VERSION 5.7 ;
  NOWIREEXTENSIONATPIN ON ;
  DIVIDERCHAR "/" ;
  BUSBITCHARS "[]" ;
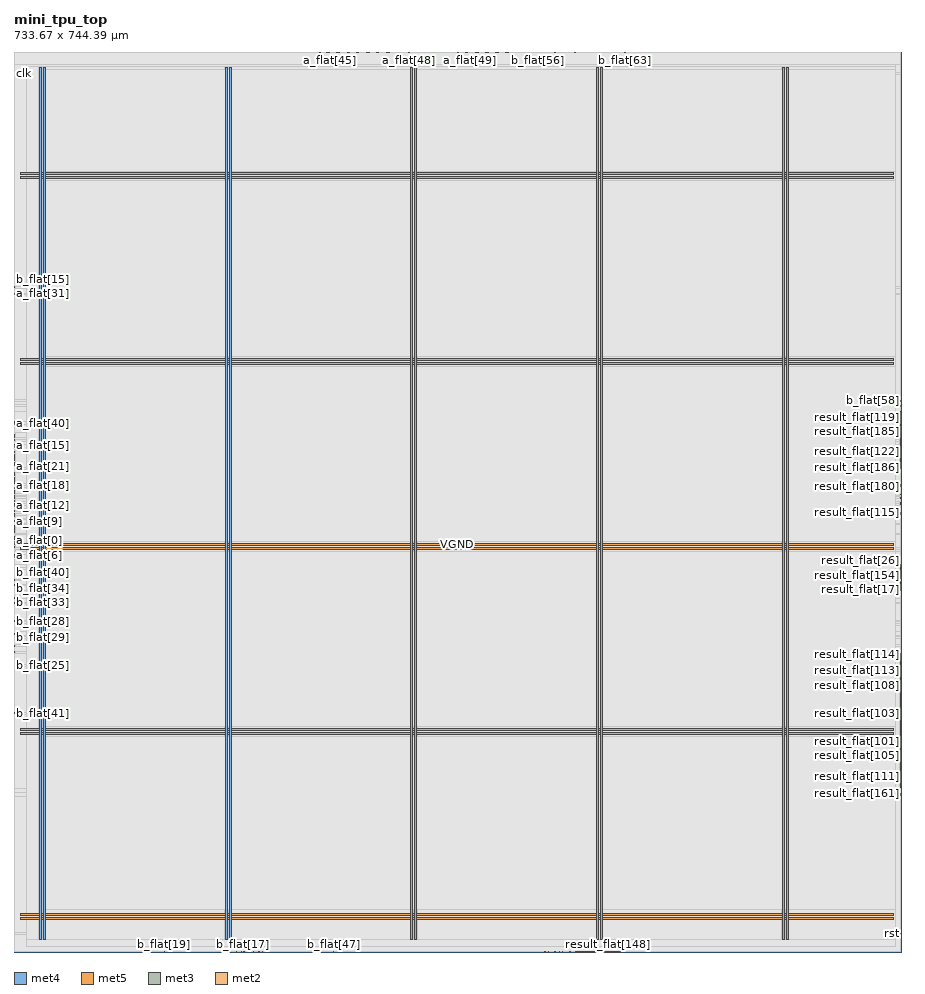
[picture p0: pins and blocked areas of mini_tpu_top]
MACRO mini_tpu_top
  CLASS BLOCK ;
  FOREIGN mini_tpu_top ;
  ORIGIN 0.000 0.000 ;
  SIZE 733.670 BY 744.390 ;
  PIN VGND
    DIRECTION INOUT ;
    USE GROUND ;
    PORT
      LAYER met4 ;
        RECT 24.340 10.640 25.940 731.920 ;
    END
    PORT
      LAYER met4 ;
        RECT 177.940 10.640 179.540 731.920 ;
    END
    PORT
      LAYER met4 ;
        RECT 331.540 10.640 333.140 731.920 ;
    END
    PORT
      LAYER met4 ;
        RECT 485.140 10.640 486.740 731.920 ;
    END
    PORT
      LAYER met4 ;
        RECT 638.740 10.640 640.340 731.920 ;
    END
    PORT
      LAYER met5 ;
        RECT 5.520 30.030 727.720 31.630 ;
    END
    PORT
      LAYER met5 ;
        RECT 5.520 183.210 727.720 184.810 ;
    END
    PORT
      LAYER met5 ;
        RECT 5.520 336.390 727.720 337.990 ;
    END
    PORT
      LAYER met5 ;
        RECT 5.520 489.570 727.720 491.170 ;
    END
    PORT
      LAYER met5 ;
        RECT 5.520 642.750 727.720 644.350 ;
    END
  END VGND
  PIN VPWR
    DIRECTION INOUT ;
    USE POWER ;
    PORT
      LAYER met4 ;
        RECT 21.040 10.640 22.640 731.920 ;
    END
    PORT
      LAYER met4 ;
        RECT 174.640 10.640 176.240 731.920 ;
    END
    PORT
      LAYER met4 ;
        RECT 328.240 10.640 329.840 731.920 ;
    END
    PORT
      LAYER met4 ;
        RECT 481.840 10.640 483.440 731.920 ;
    END
    PORT
      LAYER met4 ;
        RECT 635.440 10.640 637.040 731.920 ;
    END
    PORT
      LAYER met5 ;
        RECT 5.520 26.730 727.720 28.330 ;
    END
    PORT
      LAYER met5 ;
        RECT 5.520 179.910 727.720 181.510 ;
    END
    PORT
      LAYER met5 ;
        RECT 5.520 333.090 727.720 334.690 ;
    END
    PORT
      LAYER met5 ;
        RECT 5.520 486.270 727.720 487.870 ;
    END
    PORT
      LAYER met5 ;
        RECT 5.520 639.450 727.720 641.050 ;
    END
  END VPWR
  PIN a_flat[0]
    DIRECTION INPUT ;
    USE SIGNAL ;
    ANTENNAGATEAREA 0.213000 ;
    PORT
      LAYER met3 ;
        RECT 0.000 340.040 0.600 340.640 ;
    END
  END a_flat[0]
  PIN a_flat[10]
    DIRECTION INPUT ;
    USE SIGNAL ;
    ANTENNAGATEAREA 0.213000 ;
    PORT
      LAYER met3 ;
        RECT 0.000 355.000 0.600 355.600 ;
    END
  END a_flat[10]
  PIN a_flat[11]
    DIRECTION INPUT ;
    USE SIGNAL ;
    ANTENNAGATEAREA 0.647700 ;
    ANTENNADIFFAREA 0.434700 ;
    PORT
      LAYER met3 ;
        RECT 0.000 348.200 0.600 348.800 ;
    END
  END a_flat[11]
  PIN a_flat[12]
    DIRECTION INPUT ;
    USE SIGNAL ;
    ANTENNAGATEAREA 0.213000 ;
    PORT
      LAYER met3 ;
        RECT 0.000 368.600 0.600 369.200 ;
    END
  END a_flat[12]
  PIN a_flat[13]
    DIRECTION INPUT ;
    USE SIGNAL ;
    ANTENNAGATEAREA 0.213000 ;
    PORT
      LAYER met3 ;
        RECT 0.000 359.080 0.600 359.680 ;
    END
  END a_flat[13]
  PIN a_flat[14]
    DIRECTION INPUT ;
    USE SIGNAL ;
    ANTENNAGATEAREA 0.213000 ;
    PORT
      LAYER met3 ;
        RECT 0.000 344.120 0.600 344.720 ;
    END
  END a_flat[14]
  PIN a_flat[15]
    DIRECTION INPUT ;
    USE SIGNAL ;
    ANTENNAGATEAREA 0.213000 ;
    PORT
      LAYER met3 ;
        RECT 0.000 418.920 0.600 419.520 ;
    END
  END a_flat[15]
  PIN a_flat[16]
    DIRECTION INPUT ;
    USE SIGNAL ;
    ANTENNAGATEAREA 0.213000 ;
    PORT
      LAYER met3 ;
        RECT 0.000 405.320 0.600 405.920 ;
    END
  END a_flat[16]
  PIN a_flat[17]
    DIRECTION INPUT ;
    USE SIGNAL ;
    ANTENNAGATEAREA 0.647700 ;
    ANTENNADIFFAREA 0.434700 ;
    PORT
      LAYER met3 ;
        RECT 0.000 335.960 0.600 336.560 ;
    END
  END a_flat[17]
  PIN a_flat[18]
    DIRECTION INPUT ;
    USE SIGNAL ;
    ANTENNAGATEAREA 0.213000 ;
    PORT
      LAYER met3 ;
        RECT 0.000 379.480 0.600 380.080 ;
    END
  END a_flat[18]
  PIN a_flat[19]
    DIRECTION INPUT ;
    USE SIGNAL ;
    ANTENNAGATEAREA 0.213000 ;
    PORT
      LAYER met3 ;
        RECT 0.000 394.440 0.600 395.040 ;
    END
  END a_flat[19]
  PIN a_flat[1]
    DIRECTION INPUT ;
    USE SIGNAL ;
    ANTENNAGATEAREA 0.213000 ;
    PORT
      LAYER met3 ;
        RECT 0.000 341.400 0.600 342.000 ;
    END
  END a_flat[1]
  PIN a_flat[20]
    DIRECTION INPUT ;
    USE SIGNAL ;
    ANTENNAGATEAREA 0.213000 ;
    PORT
      LAYER met3 ;
        RECT 0.000 378.120 0.600 378.720 ;
    END
  END a_flat[20]
  PIN a_flat[21]
    DIRECTION INPUT ;
    USE SIGNAL ;
    ANTENNAGATEAREA 0.213000 ;
    PORT
      LAYER met3 ;
        RECT 0.000 401.240 0.600 401.840 ;
    END
  END a_flat[21]
  PIN a_flat[22]
    DIRECTION INPUT ;
    USE SIGNAL ;
    ANTENNAGATEAREA 0.213000 ;
    PORT
      LAYER met3 ;
        RECT 0.000 382.200 0.600 382.800 ;
    END
  END a_flat[22]
  PIN a_flat[23]
    DIRECTION INPUT ;
    USE SIGNAL ;
    ANTENNAGATEAREA 0.213000 ;
    PORT
      LAYER met3 ;
        RECT 0.000 427.080 0.600 427.680 ;
    END
  END a_flat[23]
  PIN a_flat[24]
    DIRECTION INPUT ;
    USE SIGNAL ;
    ANTENNAGATEAREA 0.213000 ;
    PORT
      LAYER met3 ;
        RECT 0.000 389.000 0.600 389.600 ;
    END
  END a_flat[24]
  PIN a_flat[25]
    DIRECTION INPUT ;
    USE SIGNAL ;
    ANTENNAGATEAREA 0.213000 ;
    PORT
      LAYER met3 ;
        RECT 0.000 375.400 0.600 376.000 ;
    END
  END a_flat[25]
  PIN a_flat[26]
    DIRECTION INPUT ;
    USE SIGNAL ;
    ANTENNAGATEAREA 0.213000 ;
    PORT
      LAYER met3 ;
        RECT 0.000 406.680 0.600 407.280 ;
    END
  END a_flat[26]
  PIN a_flat[27]
    DIRECTION INPUT ;
    USE SIGNAL ;
    ANTENNAGATEAREA 0.213000 ;
    PORT
      LAYER met3 ;
        RECT 0.000 395.800 0.600 396.400 ;
    END
  END a_flat[27]
  PIN a_flat[28]
    DIRECTION INPUT ;
    USE SIGNAL ;
    ANTENNAGATEAREA 0.213000 ;
    PORT
      LAYER met3 ;
        RECT 0.000 437.960 0.600 438.560 ;
    END
  END a_flat[28]
  PIN a_flat[29]
    DIRECTION INPUT ;
    USE SIGNAL ;
    ANTENNAGATEAREA 0.213000 ;
    PORT
      LAYER met3 ;
        RECT 0.000 417.560 0.600 418.160 ;
    END
  END a_flat[29]
  PIN a_flat[2]
    DIRECTION INPUT ;
    USE SIGNAL ;
    ANTENNAGATEAREA 0.213000 ;
    PORT
      LAYER met3 ;
        RECT 0.000 337.320 0.600 337.920 ;
    END
  END a_flat[2]
  PIN a_flat[30]
    DIRECTION INPUT ;
    USE SIGNAL ;
    ANTENNAGATEAREA 0.213000 ;
    PORT
      LAYER met3 ;
        RECT 0.000 386.280 0.600 386.880 ;
    END
  END a_flat[30]
  PIN a_flat[31]
    DIRECTION INPUT ;
    USE SIGNAL ;
    ANTENNAGATEAREA 0.213000 ;
    PORT
      LAYER met3 ;
        RECT 0.000 544.040 0.600 544.640 ;
    END
  END a_flat[31]
  PIN a_flat[32]
    DIRECTION INPUT ;
    USE SIGNAL ;
    ANTENNAGATEAREA 0.213000 ;
    PORT
      LAYER met2 ;
        RECT 266.890 744.110 267.170 744.390 ;
    END
  END a_flat[32]
  PIN a_flat[33]
    DIRECTION INPUT ;
    USE SIGNAL ;
    ANTENNAGATEAREA 0.213000 ;
    PORT
      LAYER met3 ;
        RECT 0.000 416.200 0.600 416.800 ;
    END
  END a_flat[33]
  PIN a_flat[34]
    DIRECTION INPUT ;
    USE SIGNAL ;
    ANTENNAGATEAREA 0.213000 ;
    PORT
      LAYER met2 ;
        RECT 264.130 744.110 264.410 744.390 ;
    END
  END a_flat[34]
  PIN a_flat[35]
    DIRECTION INPUT ;
    USE SIGNAL ;
    ANTENNAGATEAREA 0.213000 ;
    PORT
      LAYER met3 ;
        RECT 0.000 383.560 0.600 384.160 ;
    END
  END a_flat[35]
  PIN a_flat[36]
    DIRECTION INPUT ;
    USE SIGNAL ;
    ANTENNAGATEAREA 0.213000 ;
    PORT
      LAYER met3 ;
        RECT 0.000 387.640 0.600 388.240 ;
    END
  END a_flat[36]
  PIN a_flat[37]
    DIRECTION INPUT ;
    USE SIGNAL ;
    ANTENNAGATEAREA 0.213000 ;
    PORT
      LAYER met2 ;
        RECT 245.730 744.110 246.010 744.390 ;
    END
  END a_flat[37]
  PIN a_flat[38]
    DIRECTION INPUT ;
    USE SIGNAL ;
    ANTENNAGATEAREA 0.213000 ;
    PORT
      LAYER met3 ;
        RECT 0.000 409.400 0.600 410.000 ;
    END
  END a_flat[38]
  PIN a_flat[39]
    DIRECTION INPUT ;
    USE SIGNAL ;
    ANTENNAGATEAREA 0.213000 ;
    PORT
      LAYER met2 ;
        RECT 250.330 744.110 250.610 744.390 ;
    END
  END a_flat[39]
  PIN a_flat[3]
    DIRECTION INPUT ;
    USE SIGNAL ;
    ANTENNAGATEAREA 0.213000 ;
    PORT
      LAYER met3 ;
        RECT 0.000 346.840 0.600 347.440 ;
    END
  END a_flat[3]
  PIN a_flat[40]
    DIRECTION INPUT ;
    USE SIGNAL ;
    ANTENNAGATEAREA 0.213000 ;
    PORT
      LAYER met3 ;
        RECT 0.000 436.600 0.600 437.200 ;
    END
  END a_flat[40]
  PIN a_flat[41]
    DIRECTION INPUT ;
    USE SIGNAL ;
    ANTENNAGATEAREA 0.213000 ;
    PORT
      LAYER met2 ;
        RECT 283.450 744.110 283.730 744.390 ;
    END
  END a_flat[41]
  PIN a_flat[42]
    DIRECTION INPUT ;
    USE SIGNAL ;
    ANTENNAGATEAREA 0.213000 ;
    PORT
      LAYER met3 ;
        RECT 0.000 425.720 0.600 426.320 ;
    END
  END a_flat[42]
  PIN a_flat[43]
    DIRECTION INPUT ;
    USE SIGNAL ;
    ANTENNAGATEAREA 0.213000 ;
    PORT
      LAYER met3 ;
        RECT 0.000 408.040 0.600 408.640 ;
    END
  END a_flat[43]
  PIN a_flat[44]
    DIRECTION INPUT ;
    USE SIGNAL ;
    ANTENNAGATEAREA 0.213000 ;
    PORT
      LAYER met3 ;
        RECT 0.000 402.600 0.600 403.200 ;
    END
  END a_flat[44]
  PIN a_flat[45]
    DIRECTION INPUT ;
    USE SIGNAL ;
    ANTENNAGATEAREA 0.213000 ;
    PORT
      LAYER met2 ;
        RECT 261.370 744.110 261.650 744.390 ;
    END
  END a_flat[45]
  PIN a_flat[46]
    DIRECTION INPUT ;
    USE SIGNAL ;
    ANTENNAGATEAREA 0.213000 ;
    PORT
      LAYER met3 ;
        RECT 0.000 428.440 0.600 429.040 ;
    END
  END a_flat[46]
  PIN a_flat[47]
    DIRECTION INPUT ;
    USE SIGNAL ;
    ANTENNAGATEAREA 0.213000 ;
    PORT
      LAYER met3 ;
        RECT 0.000 391.720 0.600 392.320 ;
    END
  END a_flat[47]
  PIN a_flat[48]
    DIRECTION INPUT ;
    USE SIGNAL ;
    ANTENNAGATEAREA 0.213000 ;
    PORT
      LAYER met2 ;
        RECT 326.690 744.110 326.970 744.390 ;
    END
  END a_flat[48]
  PIN a_flat[49]
    DIRECTION INPUT ;
    USE SIGNAL ;
    ANTENNAGATEAREA 0.213000 ;
    PORT
      LAYER met2 ;
        RECT 377.290 744.110 377.570 744.390 ;
    END
  END a_flat[49]
  PIN a_flat[4]
    DIRECTION INPUT ;
    USE SIGNAL ;
    ANTENNAGATEAREA 0.213000 ;
    PORT
      LAYER met3 ;
        RECT 0.000 352.280 0.600 352.880 ;
    END
  END a_flat[4]
  PIN a_flat[50]
    DIRECTION INPUT ;
    USE SIGNAL ;
    ANTENNAGATEAREA 0.213000 ;
    PORT
      LAYER met2 ;
        RECT 330.370 744.110 330.650 744.390 ;
    END
  END a_flat[50]
  PIN a_flat[51]
    DIRECTION INPUT ;
    USE SIGNAL ;
    ANTENNAGATEAREA 0.213000 ;
    PORT
      LAYER met2 ;
        RECT 374.530 744.110 374.810 744.390 ;
    END
  END a_flat[51]
  PIN a_flat[52]
    DIRECTION INPUT ;
    USE SIGNAL ;
    ANTENNAGATEAREA 0.213000 ;
    PORT
      LAYER met2 ;
        RECT 352.450 744.110 352.730 744.390 ;
    END
  END a_flat[52]
  PIN a_flat[53]
    DIRECTION INPUT ;
    USE SIGNAL ;
    ANTENNAGATEAREA 0.213000 ;
    PORT
      LAYER met2 ;
        RECT 308.290 744.110 308.570 744.390 ;
    END
  END a_flat[53]
  PIN a_flat[54]
    DIRECTION INPUT ;
    USE SIGNAL ;
    ANTENNAGATEAREA 0.213000 ;
    PORT
      LAYER met2 ;
        RECT 319.330 744.110 319.610 744.390 ;
    END
  END a_flat[54]
  PIN a_flat[55]
    DIRECTION INPUT ;
    USE SIGNAL ;
    ANTENNAGATEAREA 0.213000 ;
    PORT
      LAYER met2 ;
        RECT 310.130 744.110 310.410 744.390 ;
    END
  END a_flat[55]
  PIN a_flat[56]
    DIRECTION INPUT ;
    USE SIGNAL ;
    ANTENNAGATEAREA 0.213000 ;
    PORT
      LAYER met2 ;
        RECT 300.010 744.110 300.290 744.390 ;
    END
  END a_flat[56]
  PIN a_flat[57]
    DIRECTION INPUT ;
    USE SIGNAL ;
    ANTENNAGATEAREA 0.213000 ;
    PORT
      LAYER met2 ;
        RECT 300.930 744.110 301.210 744.390 ;
    END
  END a_flat[57]
  PIN a_flat[58]
    DIRECTION INPUT ;
    USE SIGNAL ;
    ANTENNAGATEAREA 0.647700 ;
    ANTENNADIFFAREA 0.434700 ;
    PORT
      LAYER met2 ;
        RECT 293.570 744.110 293.850 744.390 ;
    END
  END a_flat[58]
  PIN a_flat[59]
    DIRECTION INPUT ;
    USE SIGNAL ;
    ANTENNAGATEAREA 0.213000 ;
    PORT
      LAYER met2 ;
        RECT 279.770 744.110 280.050 744.390 ;
    END
  END a_flat[59]
  PIN a_flat[5]
    DIRECTION INPUT ;
    USE SIGNAL ;
    ANTENNAGATEAREA 0.213000 ;
    PORT
      LAYER met3 ;
        RECT 0.000 338.680 0.600 339.280 ;
    END
  END a_flat[5]
  PIN a_flat[60]
    DIRECTION INPUT ;
    USE SIGNAL ;
    ANTENNAGATEAREA 0.213000 ;
    PORT
      LAYER met2 ;
        RECT 288.050 744.110 288.330 744.390 ;
    END
  END a_flat[60]
  PIN a_flat[61]
    DIRECTION INPUT ;
    USE SIGNAL ;
    ANTENNAGATEAREA 0.213000 ;
    PORT
      LAYER met2 ;
        RECT 282.530 744.110 282.810 744.390 ;
    END
  END a_flat[61]
  PIN a_flat[62]
    DIRECTION INPUT ;
    USE SIGNAL ;
    ANTENNAGATEAREA 0.213000 ;
    PORT
      LAYER met2 ;
        RECT 277.930 744.110 278.210 744.390 ;
    END
  END a_flat[62]
  PIN a_flat[63]
    DIRECTION INPUT ;
    USE SIGNAL ;
    ANTENNAGATEAREA 0.213000 ;
    PORT
      LAYER met3 ;
        RECT 0.000 325.080 0.600 325.680 ;
    END
  END a_flat[63]
  PIN a_flat[6]
    DIRECTION INPUT ;
    USE SIGNAL ;
    ANTENNAGATEAREA 0.213000 ;
    PORT
      LAYER met3 ;
        RECT 0.000 327.800 0.600 328.400 ;
    END
  END a_flat[6]
  PIN a_flat[7]
    DIRECTION INPUT ;
    USE SIGNAL ;
    ANTENNAGATEAREA 0.213000 ;
    PORT
      LAYER met3 ;
        RECT 0.000 350.920 0.600 351.520 ;
    END
  END a_flat[7]
  PIN a_flat[8]
    DIRECTION INPUT ;
    USE SIGNAL ;
    ANTENNAGATEAREA 0.213000 ;
    PORT
      LAYER met3 ;
        RECT 0.000 342.760 0.600 343.360 ;
    END
  END a_flat[8]
  PIN a_flat[9]
    DIRECTION INPUT ;
    USE SIGNAL ;
    ANTENNAGATEAREA 0.213000 ;
    PORT
      LAYER met3 ;
        RECT 0.000 361.800 0.600 362.400 ;
    END
  END a_flat[9]
  PIN b_flat[0]
    DIRECTION INPUT ;
    USE SIGNAL ;
    ANTENNAGATEAREA 0.213000 ;
    PORT
      LAYER met3 ;
        RECT 0.000 372.680 0.600 373.280 ;
    END
  END b_flat[0]
  PIN b_flat[10]
    DIRECTION INPUT ;
    USE SIGNAL ;
    ANTENNAGATEAREA 0.213000 ;
    PORT
      LAYER met3 ;
        RECT 0.000 412.120 0.600 412.720 ;
    END
  END b_flat[10]
  PIN b_flat[11]
    DIRECTION INPUT ;
    USE SIGNAL ;
    ANTENNAGATEAREA 0.213000 ;
    PORT
      LAYER met3 ;
        RECT 0.000 390.360 0.600 390.960 ;
    END
  END b_flat[11]
  PIN b_flat[12]
    DIRECTION INPUT ;
    USE SIGNAL ;
    ANTENNAGATEAREA 0.213000 ;
    PORT
      LAYER met3 ;
        RECT 0.000 413.480 0.600 414.080 ;
    END
  END b_flat[12]
  PIN b_flat[13]
    DIRECTION INPUT ;
    USE SIGNAL ;
    ANTENNAGATEAREA 0.213000 ;
    PORT
      LAYER met3 ;
        RECT 0.000 410.760 0.600 411.360 ;
    END
  END b_flat[13]
  PIN b_flat[14]
    DIRECTION INPUT ;
    USE SIGNAL ;
    ANTENNAGATEAREA 0.213000 ;
    PORT
      LAYER met3 ;
        RECT 0.000 403.960 0.600 404.560 ;
    END
  END b_flat[14]
  PIN b_flat[15]
    DIRECTION INPUT ;
    USE SIGNAL ;
    ANTENNAGATEAREA 0.213000 ;
    PORT
      LAYER met3 ;
        RECT 0.000 549.480 0.600 550.080 ;
    END
  END b_flat[15]
  PIN b_flat[16]
    DIRECTION INPUT ;
    USE SIGNAL ;
    ANTENNAGATEAREA 0.213000 ;
    PORT
      LAYER met2 ;
        RECT 184.090 0.000 184.370 0.280 ;
    END
  END b_flat[16]
  PIN b_flat[17]
    DIRECTION INPUT ;
    USE SIGNAL ;
    ANTENNAGATEAREA 0.213000 ;
    PORT
      LAYER met2 ;
        RECT 189.610 0.000 189.890 0.280 ;
    END
  END b_flat[17]
  PIN b_flat[18]
    DIRECTION INPUT ;
    USE SIGNAL ;
    ANTENNAGATEAREA 0.213000 ;
    PORT
      LAYER met2 ;
        RECT 187.770 0.000 188.050 0.280 ;
    END
  END b_flat[18]
  PIN b_flat[19]
    DIRECTION INPUT ;
    USE SIGNAL ;
    ANTENNAGATEAREA 0.213000 ;
    PORT
      LAYER met2 ;
        RECT 124.290 0.000 124.570 0.280 ;
    END
  END b_flat[19]
  PIN b_flat[1]
    DIRECTION INPUT ;
    USE SIGNAL ;
    ANTENNAGATEAREA 0.213000 ;
    PORT
      LAYER met3 ;
        RECT 0.000 356.360 0.600 356.960 ;
    END
  END b_flat[1]
  PIN b_flat[20]
    DIRECTION INPUT ;
    USE SIGNAL ;
    ANTENNAGATEAREA 0.213000 ;
    PORT
      LAYER met2 ;
        RECT 177.650 0.000 177.930 0.280 ;
    END
  END b_flat[20]
  PIN b_flat[21]
    DIRECTION INPUT ;
    USE SIGNAL ;
    ANTENNAGATEAREA 0.213000 ;
    PORT
      LAYER met2 ;
        RECT 205.250 0.000 205.530 0.280 ;
    END
  END b_flat[21]
  PIN b_flat[22]
    DIRECTION INPUT ;
    USE SIGNAL ;
    ANTENNAGATEAREA 0.213000 ;
    PORT
      LAYER met2 ;
        RECT 193.290 0.000 193.570 0.280 ;
    END
  END b_flat[22]
  PIN b_flat[23]
    DIRECTION INPUT ;
    USE SIGNAL ;
    ANTENNAGATEAREA 0.213000 ;
    PORT
      LAYER met2 ;
        RECT 190.530 0.000 190.810 0.280 ;
    END
  END b_flat[23]
  PIN b_flat[24]
    DIRECTION INPUT ;
    USE SIGNAL ;
    ANTENNAGATEAREA 0.213000 ;
    PORT
      LAYER met2 ;
        RECT 197.890 0.000 198.170 0.280 ;
    END
  END b_flat[24]
  PIN b_flat[25]
    DIRECTION INPUT ;
    USE SIGNAL ;
    ANTENNAGATEAREA 0.213000 ;
    PORT
      LAYER met3 ;
        RECT 0.000 236.680 0.600 237.280 ;
    END
  END b_flat[25]
  PIN b_flat[26]
    DIRECTION INPUT ;
    USE SIGNAL ;
    ANTENNAGATEAREA 0.213000 ;
    PORT
      LAYER met2 ;
        RECT 209.850 0.000 210.130 0.280 ;
    END
  END b_flat[26]
  PIN b_flat[27]
    DIRECTION INPUT ;
    USE SIGNAL ;
    ANTENNAGATEAREA 0.213000 ;
    PORT
      LAYER met3 ;
        RECT 0.000 253.000 0.600 253.600 ;
    END
  END b_flat[27]
  PIN b_flat[28]
    DIRECTION INPUT ;
    USE SIGNAL ;
    ANTENNAGATEAREA 0.213000 ;
    PORT
      LAYER met3 ;
        RECT 0.000 273.400 0.600 274.000 ;
    END
  END b_flat[28]
  PIN b_flat[29]
    DIRECTION INPUT ;
    USE SIGNAL ;
    ANTENNAGATEAREA 0.213000 ;
    PORT
      LAYER met3 ;
        RECT 0.000 259.800 0.600 260.400 ;
    END
  END b_flat[29]
  PIN b_flat[2]
    DIRECTION INPUT ;
    USE SIGNAL ;
    ANTENNAGATEAREA 0.213000 ;
    PORT
      LAYER met3 ;
        RECT 0.000 376.760 0.600 377.360 ;
    END
  END b_flat[2]
  PIN b_flat[30]
    DIRECTION INPUT ;
    USE SIGNAL ;
    ANTENNAGATEAREA 0.213000 ;
    PORT
      LAYER met3 ;
        RECT 0.000 262.520 0.600 263.120 ;
    END
  END b_flat[30]
  PIN b_flat[31]
    DIRECTION INPUT ;
    USE SIGNAL ;
    ANTENNAGATEAREA 0.213000 ;
    PORT
      LAYER met3 ;
        RECT 0.000 247.560 0.600 248.160 ;
    END
  END b_flat[31]
  PIN b_flat[32]
    DIRECTION INPUT ;
    USE SIGNAL ;
    ANTENNAGATEAREA 0.213000 ;
    PORT
      LAYER met3 ;
        RECT 0.000 292.440 0.600 293.040 ;
    END
  END b_flat[32]
  PIN b_flat[33]
    DIRECTION INPUT ;
    USE SIGNAL ;
    ANTENNAGATEAREA 0.213000 ;
    PORT
      LAYER met3 ;
        RECT 0.000 288.360 0.600 288.960 ;
    END
  END b_flat[33]
  PIN b_flat[34]
    DIRECTION INPUT ;
    USE SIGNAL ;
    ANTENNAGATEAREA 0.213000 ;
    PORT
      LAYER met3 ;
        RECT 0.000 293.800 0.600 294.400 ;
    END
  END b_flat[34]
  PIN b_flat[35]
    DIRECTION INPUT ;
    USE SIGNAL ;
    ANTENNAGATEAREA 0.213000 ;
    PORT
      LAYER met3 ;
        RECT 0.000 349.560 0.600 350.160 ;
    END
  END b_flat[35]
  PIN b_flat[36]
    DIRECTION INPUT ;
    USE SIGNAL ;
    ANTENNAGATEAREA 0.213000 ;
    PORT
      LAYER met3 ;
        RECT 0.000 367.240 0.600 367.840 ;
    END
  END b_flat[36]
  PIN b_flat[37]
    DIRECTION INPUT ;
    USE SIGNAL ;
    ANTENNAGATEAREA 0.213000 ;
    PORT
      LAYER met3 ;
        RECT 0.000 374.040 0.600 374.640 ;
    END
  END b_flat[37]
  PIN b_flat[38]
    DIRECTION INPUT ;
    USE SIGNAL ;
    ANTENNAGATEAREA 0.213000 ;
    PORT
      LAYER met3 ;
        RECT 0.000 369.960 0.600 370.560 ;
    END
  END b_flat[38]
  PIN b_flat[39]
    DIRECTION INPUT ;
    USE SIGNAL ;
    ANTENNAGATEAREA 0.213000 ;
    PORT
      LAYER met3 ;
        RECT 0.000 331.880 0.600 332.480 ;
    END
  END b_flat[39]
  PIN b_flat[3]
    DIRECTION INPUT ;
    USE SIGNAL ;
    ANTENNAGATEAREA 0.213000 ;
    PORT
      LAYER met3 ;
        RECT 0.000 364.520 0.600 365.120 ;
    END
  END b_flat[3]
  PIN b_flat[40]
    DIRECTION INPUT ;
    USE SIGNAL ;
    ANTENNAGATEAREA 0.213000 ;
    PORT
      LAYER met3 ;
        RECT 0.000 307.400 0.600 308.000 ;
    END
  END b_flat[40]
  PIN b_flat[41]
    DIRECTION INPUT ;
    USE SIGNAL ;
    ANTENNAGATEAREA 0.213000 ;
    PORT
      LAYER met3 ;
        RECT 0.000 197.240 0.600 197.840 ;
    END
  END b_flat[41]
  PIN b_flat[42]
    DIRECTION INPUT ;
    USE SIGNAL ;
    ANTENNAGATEAREA 0.213000 ;
    PORT
      LAYER met3 ;
        RECT 0.000 303.320 0.600 303.920 ;
    END
  END b_flat[42]
  PIN b_flat[43]
    DIRECTION INPUT ;
    USE SIGNAL ;
    ANTENNAGATEAREA 0.213000 ;
    PORT
      LAYER met2 ;
        RECT 202.490 0.000 202.770 0.280 ;
    END
  END b_flat[43]
  PIN b_flat[44]
    DIRECTION INPUT ;
    USE SIGNAL ;
    ANTENNAGATEAREA 0.213000 ;
    PORT
      LAYER met3 ;
        RECT 0.000 316.920 0.600 317.520 ;
    END
  END b_flat[44]
  PIN b_flat[45]
    DIRECTION INPUT ;
    USE SIGNAL ;
    ANTENNAGATEAREA 0.213000 ;
    PORT
      LAYER met3 ;
        RECT 0.000 263.880 0.600 264.480 ;
    END
  END b_flat[45]
  PIN b_flat[46]
    DIRECTION INPUT ;
    USE SIGNAL ;
    ANTENNAGATEAREA 0.213000 ;
    PORT
      LAYER met3 ;
        RECT 0.000 270.680 0.600 271.280 ;
    END
  END b_flat[46]
  PIN b_flat[47]
    DIRECTION INPUT ;
    USE SIGNAL ;
    ANTENNAGATEAREA 0.213000 ;
    PORT
      LAYER met2 ;
        RECT 264.130 0.000 264.410 0.280 ;
    END
  END b_flat[47]
  PIN b_flat[48]
    DIRECTION INPUT ;
    USE SIGNAL ;
    ANTENNAGATEAREA 0.213000 ;
    PORT
      LAYER met2 ;
        RECT 403.050 744.110 403.330 744.390 ;
    END
  END b_flat[48]
  PIN b_flat[49]
    DIRECTION INPUT ;
    USE SIGNAL ;
    ANTENNAGATEAREA 0.647700 ;
    ANTENNADIFFAREA 0.434700 ;
    PORT
      LAYER met2 ;
        RECT 387.410 744.110 387.690 744.390 ;
    END
  END b_flat[49]
  PIN b_flat[4]
    DIRECTION INPUT ;
    USE SIGNAL ;
    ANTENNAGATEAREA 0.213000 ;
    PORT
      LAYER met3 ;
        RECT 0.000 360.440 0.600 361.040 ;
    END
  END b_flat[4]
  PIN b_flat[50]
    DIRECTION INPUT ;
    USE SIGNAL ;
    ANTENNAGATEAREA 0.213000 ;
    PORT
      LAYER met2 ;
        RECT 463.770 744.110 464.050 744.390 ;
    END
  END b_flat[50]
  PIN b_flat[51]
    DIRECTION INPUT ;
    USE SIGNAL ;
    ANTENNAGATEAREA 0.213000 ;
    PORT
      LAYER met2 ;
        RECT 398.450 744.110 398.730 744.390 ;
    END
  END b_flat[51]
  PIN b_flat[52]
    DIRECTION INPUT ;
    USE SIGNAL ;
    ANTENNAGATEAREA 0.213000 ;
    PORT
      LAYER met2 ;
        RECT 393.850 744.110 394.130 744.390 ;
    END
  END b_flat[52]
  PIN b_flat[53]
    DIRECTION INPUT ;
    USE SIGNAL ;
    ANTENNAGATEAREA 0.647700 ;
    ANTENNADIFFAREA 0.434700 ;
    PORT
      LAYER met2 ;
        RECT 402.130 744.110 402.410 744.390 ;
    END
  END b_flat[53]
  PIN b_flat[54]
    DIRECTION INPUT ;
    USE SIGNAL ;
    ANTENNAGATEAREA 0.647700 ;
    ANTENNADIFFAREA 0.434700 ;
    PORT
      LAYER met2 ;
        RECT 388.330 744.110 388.610 744.390 ;
    END
  END b_flat[54]
  PIN b_flat[55]
    DIRECTION INPUT ;
    USE SIGNAL ;
    ANTENNAGATEAREA 0.647700 ;
    ANTENNADIFFAREA 0.434700 ;
    PORT
      LAYER met2 ;
        RECT 407.650 744.110 407.930 744.390 ;
    END
  END b_flat[55]
  PIN b_flat[56]
    DIRECTION INPUT ;
    USE SIGNAL ;
    ANTENNAGATEAREA 0.213000 ;
    PORT
      LAYER met2 ;
        RECT 433.410 744.110 433.690 744.390 ;
    END
  END b_flat[56]
  PIN b_flat[57]
    DIRECTION INPUT ;
    USE SIGNAL ;
    ANTENNAGATEAREA 0.213000 ;
    PORT
      LAYER met2 ;
        RECT 471.130 744.110 471.410 744.390 ;
    END
  END b_flat[57]
  PIN b_flat[58]
    DIRECTION INPUT ;
    USE SIGNAL ;
    ANTENNAGATEAREA 0.213000 ;
    PORT
      LAYER met3 ;
        RECT 733.070 455.640 733.670 456.240 ;
    END
  END b_flat[58]
  PIN b_flat[59]
    DIRECTION INPUT ;
    USE SIGNAL ;
    ANTENNAGATEAREA 0.647700 ;
    ANTENNADIFFAREA 0.434700 ;
    PORT
      LAYER met2 ;
        RECT 420.530 744.110 420.810 744.390 ;
    END
  END b_flat[59]
  PIN b_flat[5]
    DIRECTION INPUT ;
    USE SIGNAL ;
    ANTENNAGATEAREA 0.213000 ;
    PORT
      LAYER met3 ;
        RECT 0.000 334.600 0.600 335.200 ;
    END
  END b_flat[5]
  PIN b_flat[60]
    DIRECTION INPUT ;
    USE SIGNAL ;
    ANTENNAGATEAREA 0.213000 ;
    PORT
      LAYER met2 ;
        RECT 417.770 744.110 418.050 744.390 ;
    END
  END b_flat[60]
  PIN b_flat[61]
    DIRECTION INPUT ;
    USE SIGNAL ;
    ANTENNAGATEAREA 0.213000 ;
    PORT
      LAYER met2 ;
        RECT 408.570 744.110 408.850 744.390 ;
    END
  END b_flat[61]
  PIN b_flat[62]
    DIRECTION INPUT ;
    USE SIGNAL ;
    ANTENNAGATEAREA 0.213000 ;
    PORT
      LAYER met2 ;
        RECT 447.210 744.110 447.490 744.390 ;
    END
  END b_flat[62]
  PIN b_flat[63]
    DIRECTION INPUT ;
    USE SIGNAL ;
    ANTENNAGATEAREA 0.213000 ;
    PORT
      LAYER met2 ;
        RECT 505.170 744.110 505.450 744.390 ;
    END
  END b_flat[63]
  PIN b_flat[6]
    DIRECTION INPUT ;
    USE SIGNAL ;
    ANTENNAGATEAREA 0.213000 ;
    PORT
      LAYER met3 ;
        RECT 0.000 326.440 0.600 327.040 ;
    END
  END b_flat[6]
  PIN b_flat[7]
    DIRECTION INPUT ;
    USE SIGNAL ;
    ANTENNAGATEAREA 0.213000 ;
    PORT
      LAYER met3 ;
        RECT 0.000 423.000 0.600 423.600 ;
    END
  END b_flat[7]
  PIN b_flat[8]
    DIRECTION INPUT ;
    USE SIGNAL ;
    ANTENNAGATEAREA 0.213000 ;
    PORT
      LAYER met3 ;
        RECT 0.000 380.840 0.600 381.440 ;
    END
  END b_flat[8]
  PIN b_flat[9]
    DIRECTION INPUT ;
    USE SIGNAL ;
    ANTENNAGATEAREA 0.213000 ;
    PORT
      LAYER met3 ;
        RECT 0.000 393.080 0.600 393.680 ;
    END
  END b_flat[9]
  PIN clk
    DIRECTION INPUT ;
    USE SIGNAL ;
    ANTENNAGATEAREA 0.852000 ;
    PORT
      LAYER met3 ;
        RECT 0.000 726.280 0.600 726.880 ;
    END
  END clk
  PIN done
    DIRECTION OUTPUT ;
    USE SIGNAL ;
    ANTENNADIFFAREA 0.702900 ;
    PORT
      LAYER met2 ;
        RECT 502.410 744.110 502.690 744.390 ;
    END
  END done
  PIN result_flat[0]
    DIRECTION OUTPUT ;
    USE SIGNAL ;
    ANTENNADIFFAREA 0.702900 ;
    PORT
      LAYER met2 ;
        RECT 394.770 744.110 395.050 744.390 ;
    END
  END result_flat[0]
  PIN result_flat[100]
    DIRECTION OUTPUT ;
    USE SIGNAL ;
    ANTENNADIFFAREA 0.702900 ;
    PORT
      LAYER met3 ;
        RECT 733.070 138.760 733.670 139.360 ;
    END
  END result_flat[100]
  PIN result_flat[101]
    DIRECTION OUTPUT ;
    USE SIGNAL ;
    ANTENNADIFFAREA 0.702900 ;
    PORT
      LAYER met3 ;
        RECT 733.070 174.120 733.670 174.720 ;
    END
  END result_flat[101]
  PIN result_flat[102]
    DIRECTION OUTPUT ;
    USE SIGNAL ;
    ANTENNADIFFAREA 0.702900 ;
    PORT
      LAYER met3 ;
        RECT 733.070 141.480 733.670 142.080 ;
    END
  END result_flat[102]
  PIN result_flat[103]
    DIRECTION OUTPUT ;
    USE SIGNAL ;
    ANTENNADIFFAREA 0.702900 ;
    PORT
      LAYER met3 ;
        RECT 733.070 197.240 733.670 197.840 ;
    END
  END result_flat[103]
  PIN result_flat[104]
    DIRECTION OUTPUT ;
    USE SIGNAL ;
    ANTENNADIFFAREA 0.702900 ;
    PORT
      LAYER met3 ;
        RECT 733.070 182.280 733.670 182.880 ;
    END
  END result_flat[104]
  PIN result_flat[105]
    DIRECTION OUTPUT ;
    USE SIGNAL ;
    ANTENNADIFFAREA 0.702900 ;
    PORT
      LAYER met3 ;
        RECT 733.070 168.680 733.670 169.280 ;
    END
  END result_flat[105]
  PIN result_flat[106]
    DIRECTION OUTPUT ;
    USE SIGNAL ;
    ANTENNADIFFAREA 0.702900 ;
    PORT
      LAYER met3 ;
        RECT 733.070 190.440 733.670 191.040 ;
    END
  END result_flat[106]
  PIN result_flat[107]
    DIRECTION OUTPUT ;
    USE SIGNAL ;
    ANTENNADIFFAREA 0.702900 ;
    PORT
      LAYER met3 ;
        RECT 733.070 195.880 733.670 196.480 ;
    END
  END result_flat[107]
  PIN result_flat[108]
    DIRECTION OUTPUT ;
    USE SIGNAL ;
    ANTENNADIFFAREA 0.702900 ;
    PORT
      LAYER met3 ;
        RECT 733.070 220.360 733.670 220.960 ;
    END
  END result_flat[108]
  PIN result_flat[109]
    DIRECTION OUTPUT ;
    USE SIGNAL ;
    ANTENNADIFFAREA 0.702900 ;
    PORT
      LAYER met3 ;
        RECT 733.070 209.480 733.670 210.080 ;
    END
  END result_flat[109]
  PIN result_flat[10]
    DIRECTION OUTPUT ;
    USE SIGNAL ;
    ANTENNADIFFAREA 0.702900 ;
    PORT
      LAYER met2 ;
        RECT 290.810 744.110 291.090 744.390 ;
    END
  END result_flat[10]
  PIN result_flat[110]
    DIRECTION OUTPUT ;
    USE SIGNAL ;
    ANTENNADIFFAREA 0.702900 ;
    PORT
      LAYER met3 ;
        RECT 733.070 206.760 733.670 207.360 ;
    END
  END result_flat[110]
  PIN result_flat[111]
    DIRECTION OUTPUT ;
    USE SIGNAL ;
    ANTENNADIFFAREA 0.702900 ;
    PORT
      LAYER met3 ;
        RECT 733.070 151.000 733.670 151.600 ;
    END
  END result_flat[111]
  PIN result_flat[112]
    DIRECTION OUTPUT ;
    USE SIGNAL ;
    ANTENNADIFFAREA 0.702900 ;
    PORT
      LAYER met3 ;
        RECT 733.070 246.200 733.670 246.800 ;
    END
  END result_flat[112]
  PIN result_flat[113]
    DIRECTION OUTPUT ;
    USE SIGNAL ;
    ANTENNADIFFAREA 0.702900 ;
    PORT
      LAYER met3 ;
        RECT 733.070 232.600 733.670 233.200 ;
    END
  END result_flat[113]
  PIN result_flat[114]
    DIRECTION OUTPUT ;
    USE SIGNAL ;
    ANTENNADIFFAREA 0.702900 ;
    PORT
      LAYER met3 ;
        RECT 733.070 239.400 733.670 240.000 ;
    END
  END result_flat[114]
  PIN result_flat[115]
    DIRECTION OUTPUT ;
    USE SIGNAL ;
    ANTENNADIFFAREA 0.702900 ;
    PORT
      LAYER met3 ;
        RECT 733.070 363.160 733.670 363.760 ;
    END
  END result_flat[115]
  PIN result_flat[116]
    DIRECTION OUTPUT ;
    USE SIGNAL ;
    ANTENNADIFFAREA 0.702900 ;
    PORT
      LAYER met3 ;
        RECT 733.070 378.120 733.670 378.720 ;
    END
  END result_flat[116]
  PIN result_flat[117]
    DIRECTION OUTPUT ;
    USE SIGNAL ;
    ANTENNADIFFAREA 0.702900 ;
    PORT
      LAYER met3 ;
        RECT 733.070 231.240 733.670 231.840 ;
    END
  END result_flat[117]
  PIN result_flat[118]
    DIRECTION OUTPUT ;
    USE SIGNAL ;
    ANTENNADIFFAREA 0.702900 ;
    PORT
      LAYER met3 ;
        RECT 733.070 225.800 733.670 226.400 ;
    END
  END result_flat[118]
  PIN result_flat[119]
    DIRECTION OUTPUT ;
    USE SIGNAL ;
    ANTENNADIFFAREA 0.702900 ;
    PORT
      LAYER met3 ;
        RECT 733.070 442.040 733.670 442.640 ;
    END
  END result_flat[119]
  PIN result_flat[11]
    DIRECTION OUTPUT ;
    USE SIGNAL ;
    ANTENNADIFFAREA 0.702900 ;
    PORT
      LAYER met2 ;
        RECT 268.730 744.110 269.010 744.390 ;
    END
  END result_flat[11]
  PIN result_flat[120]
    DIRECTION OUTPUT ;
    USE SIGNAL ;
    ANTENNADIFFAREA 0.702900 ;
    PORT
      LAYER met3 ;
        RECT 733.070 417.560 733.670 418.160 ;
    END
  END result_flat[120]
  PIN result_flat[121]
    DIRECTION OUTPUT ;
    USE SIGNAL ;
    ANTENNADIFFAREA 0.702900 ;
    PORT
      LAYER met3 ;
        RECT 733.070 428.440 733.670 429.040 ;
    END
  END result_flat[121]
  PIN result_flat[122]
    DIRECTION OUTPUT ;
    USE SIGNAL ;
    ANTENNADIFFAREA 0.702900 ;
    PORT
      LAYER met3 ;
        RECT 733.070 413.480 733.670 414.080 ;
    END
  END result_flat[122]
  PIN result_flat[123]
    DIRECTION OUTPUT ;
    USE SIGNAL ;
    ANTENNADIFFAREA 0.702900 ;
    PORT
      LAYER met3 ;
        RECT 733.070 440.680 733.670 441.280 ;
    END
  END result_flat[123]
  PIN result_flat[124]
    DIRECTION OUTPUT ;
    USE SIGNAL ;
    ANTENNADIFFAREA 0.702900 ;
    PORT
      LAYER met3 ;
        RECT 733.070 416.200 733.670 416.800 ;
    END
  END result_flat[124]
  PIN result_flat[125]
    DIRECTION OUTPUT ;
    USE SIGNAL ;
    ANTENNADIFFAREA 0.702900 ;
    PORT
      LAYER met3 ;
        RECT 733.070 444.760 733.670 445.360 ;
    END
  END result_flat[125]
  PIN result_flat[126]
    DIRECTION OUTPUT ;
    USE SIGNAL ;
    ANTENNADIFFAREA 0.702900 ;
    PORT
      LAYER met3 ;
        RECT 733.070 399.880 733.670 400.480 ;
    END
  END result_flat[126]
  PIN result_flat[127]
    DIRECTION OUTPUT ;
    USE SIGNAL ;
    ANTENNADIFFAREA 0.702900 ;
    PORT
      LAYER met3 ;
        RECT 733.070 405.320 733.670 405.920 ;
    END
  END result_flat[127]
  PIN result_flat[128]
    DIRECTION OUTPUT ;
    USE SIGNAL ;
    ANTENNADIFFAREA 0.702900 ;
    PORT
      LAYER met2 ;
        RECT 409.490 744.110 409.770 744.390 ;
    END
  END result_flat[128]
  PIN result_flat[129]
    DIRECTION OUTPUT ;
    USE SIGNAL ;
    ANTENNADIFFAREA 0.702900 ;
    PORT
      LAYER met2 ;
        RECT 400.290 744.110 400.570 744.390 ;
    END
  END result_flat[129]
  PIN result_flat[12]
    DIRECTION OUTPUT ;
    USE SIGNAL ;
    ANTENNADIFFAREA 0.702900 ;
    PORT
      LAYER met2 ;
        RECT 380.050 744.110 380.330 744.390 ;
    END
  END result_flat[12]
  PIN result_flat[130]
    DIRECTION OUTPUT ;
    USE SIGNAL ;
    ANTENNADIFFAREA 0.702900 ;
    PORT
      LAYER met2 ;
        RECT 265.970 744.110 266.250 744.390 ;
    END
  END result_flat[130]
  PIN result_flat[131]
    DIRECTION OUTPUT ;
    USE SIGNAL ;
    ANTENNADIFFAREA 0.702900 ;
    PORT
      LAYER met2 ;
        RECT 399.370 744.110 399.650 744.390 ;
    END
  END result_flat[131]
  PIN result_flat[132]
    DIRECTION OUTPUT ;
    USE SIGNAL ;
    ANTENNADIFFAREA 0.702900 ;
    PORT
      LAYER met2 ;
        RECT 381.890 744.110 382.170 744.390 ;
    END
  END result_flat[132]
  PIN result_flat[133]
    DIRECTION OUTPUT ;
    USE SIGNAL ;
    ANTENNADIFFAREA 0.702900 ;
    PORT
      LAYER met2 ;
        RECT 389.250 744.110 389.530 744.390 ;
    END
  END result_flat[133]
  PIN result_flat[134]
    DIRECTION OUTPUT ;
    USE SIGNAL ;
    ANTENNADIFFAREA 0.702900 ;
    PORT
      LAYER met2 ;
        RECT 372.690 744.110 372.970 744.390 ;
    END
  END result_flat[134]
  PIN result_flat[135]
    DIRECTION OUTPUT ;
    USE SIGNAL ;
    ANTENNADIFFAREA 0.702900 ;
    PORT
      LAYER met2 ;
        RECT 401.210 744.110 401.490 744.390 ;
    END
  END result_flat[135]
  PIN result_flat[136]
    DIRECTION OUTPUT ;
    USE SIGNAL ;
    ANTENNADIFFAREA 0.702900 ;
    PORT
      LAYER met2 ;
        RECT 260.450 744.110 260.730 744.390 ;
    END
  END result_flat[136]
  PIN result_flat[137]
    DIRECTION OUTPUT ;
    USE SIGNAL ;
    ANTENNADIFFAREA 0.702900 ;
    PORT
      LAYER met2 ;
        RECT 277.010 744.110 277.290 744.390 ;
    END
  END result_flat[137]
  PIN result_flat[138]
    DIRECTION OUTPUT ;
    USE SIGNAL ;
    ANTENNADIFFAREA 0.702900 ;
    PORT
      LAYER met2 ;
        RECT 292.650 744.110 292.930 744.390 ;
    END
  END result_flat[138]
  PIN result_flat[139]
    DIRECTION OUTPUT ;
    USE SIGNAL ;
    ANTENNADIFFAREA 0.702900 ;
    PORT
      LAYER met2 ;
        RECT 269.650 744.110 269.930 744.390 ;
    END
  END result_flat[139]
  PIN result_flat[13]
    DIRECTION OUTPUT ;
    USE SIGNAL ;
    ANTENNADIFFAREA 0.702900 ;
    PORT
      LAYER met2 ;
        RECT 263.210 744.110 263.490 744.390 ;
    END
  END result_flat[13]
  PIN result_flat[140]
    DIRECTION OUTPUT ;
    USE SIGNAL ;
    ANTENNADIFFAREA 0.702900 ;
    PORT
      LAYER met2 ;
        RECT 392.010 744.110 392.290 744.390 ;
    END
  END result_flat[140]
  PIN result_flat[141]
    DIRECTION OUTPUT ;
    USE SIGNAL ;
    ANTENNADIFFAREA 0.702900 ;
    PORT
      LAYER met2 ;
        RECT 270.570 744.110 270.850 744.390 ;
    END
  END result_flat[141]
  PIN result_flat[142]
    DIRECTION OUTPUT ;
    USE SIGNAL ;
    ANTENNADIFFAREA 0.702900 ;
    PORT
      LAYER met2 ;
        RECT 281.610 744.110 281.890 744.390 ;
    END
  END result_flat[142]
  PIN result_flat[143]
    DIRECTION OUTPUT ;
    USE SIGNAL ;
    ANTENNADIFFAREA 0.702900 ;
    PORT
      LAYER met2 ;
        RECT 253.090 744.110 253.370 744.390 ;
    END
  END result_flat[143]
  PIN result_flat[144]
    DIRECTION OUTPUT ;
    USE SIGNAL ;
    ANTENNADIFFAREA 0.702900 ;
    PORT
      LAYER met2 ;
        RECT 487.690 0.000 487.970 0.280 ;
    END
  END result_flat[144]
  PIN result_flat[145]
    DIRECTION OUTPUT ;
    USE SIGNAL ;
    ANTENNADIFFAREA 0.702900 ;
    PORT
      LAYER met3 ;
        RECT 733.070 301.960 733.670 302.560 ;
    END
  END result_flat[145]
  PIN result_flat[146]
    DIRECTION OUTPUT ;
    USE SIGNAL ;
    ANTENNADIFFAREA 0.702900 ;
    PORT
      LAYER met2 ;
        RECT 447.210 0.000 447.490 0.280 ;
    END
  END result_flat[146]
  PIN result_flat[147]
    DIRECTION OUTPUT ;
    USE SIGNAL ;
    ANTENNADIFFAREA 0.702900 ;
    PORT
      LAYER met2 ;
        RECT 500.570 0.000 500.850 0.280 ;
    END
  END result_flat[147]
  PIN result_flat[148]
    DIRECTION OUTPUT ;
    USE SIGNAL ;
    ANTENNADIFFAREA 0.702900 ;
    PORT
      LAYER met2 ;
        RECT 491.370 0.000 491.650 0.280 ;
    END
  END result_flat[148]
  PIN result_flat[149]
    DIRECTION OUTPUT ;
    USE SIGNAL ;
    ANTENNADIFFAREA 0.702900 ;
    PORT
      LAYER met2 ;
        RECT 484.930 0.000 485.210 0.280 ;
    END
  END result_flat[149]
  PIN result_flat[14]
    DIRECTION OUTPUT ;
    USE SIGNAL ;
    ANTENNADIFFAREA 0.702900 ;
    PORT
      LAYER met2 ;
        RECT 287.130 744.110 287.410 744.390 ;
    END
  END result_flat[14]
  PIN result_flat[150]
    DIRECTION OUTPUT ;
    USE SIGNAL ;
    ANTENNADIFFAREA 0.702900 ;
    PORT
      LAYER met2 ;
        RECT 498.730 0.000 499.010 0.280 ;
    END
  END result_flat[150]
  PIN result_flat[151]
    DIRECTION OUTPUT ;
    USE SIGNAL ;
    ANTENNADIFFAREA 0.702900 ;
    PORT
      LAYER met2 ;
        RECT 489.530 0.000 489.810 0.280 ;
    END
  END result_flat[151]
  PIN result_flat[152]
    DIRECTION OUTPUT ;
    USE SIGNAL ;
    ANTENNADIFFAREA 0.702900 ;
    PORT
      LAYER met2 ;
        RECT 464.690 0.000 464.970 0.280 ;
    END
  END result_flat[152]
  PIN result_flat[153]
    DIRECTION OUTPUT ;
    USE SIGNAL ;
    ANTENNADIFFAREA 0.702900 ;
    PORT
      LAYER met2 ;
        RECT 482.170 0.000 482.450 0.280 ;
    END
  END result_flat[153]
  PIN result_flat[154]
    DIRECTION OUTPUT ;
    USE SIGNAL ;
    ANTENNADIFFAREA 0.702900 ;
    PORT
      LAYER met3 ;
        RECT 733.070 311.480 733.670 312.080 ;
    END
  END result_flat[154]
  PIN result_flat[155]
    DIRECTION OUTPUT ;
    USE SIGNAL ;
    ANTENNADIFFAREA 0.702900 ;
    PORT
      LAYER met2 ;
        RECT 488.610 0.000 488.890 0.280 ;
    END
  END result_flat[155]
  PIN result_flat[156]
    DIRECTION OUTPUT ;
    USE SIGNAL ;
    ANTENNADIFFAREA 0.702900 ;
    PORT
      LAYER met2 ;
        RECT 499.650 0.000 499.930 0.280 ;
    END
  END result_flat[156]
  PIN result_flat[157]
    DIRECTION OUTPUT ;
    USE SIGNAL ;
    ANTENNADIFFAREA 0.702900 ;
    PORT
      LAYER met3 ;
        RECT 733.070 319.640 733.670 320.240 ;
    END
  END result_flat[157]
  PIN result_flat[158]
    DIRECTION OUTPUT ;
    USE SIGNAL ;
    ANTENNADIFFAREA 0.702900 ;
    PORT
      LAYER met2 ;
        RECT 468.370 0.000 468.650 0.280 ;
    END
  END result_flat[158]
  PIN result_flat[159]
    DIRECTION OUTPUT ;
    USE SIGNAL ;
    ANTENNADIFFAREA 0.702900 ;
    PORT
      LAYER met3 ;
        RECT 733.070 308.760 733.670 309.360 ;
    END
  END result_flat[159]
  PIN result_flat[15]
    DIRECTION OUTPUT ;
    USE SIGNAL ;
    ANTENNADIFFAREA 0.702900 ;
    PORT
      LAYER met2 ;
        RECT 255.850 744.110 256.130 744.390 ;
    END
  END result_flat[15]
  PIN result_flat[160]
    DIRECTION OUTPUT ;
    USE SIGNAL ;
    ANTENNADIFFAREA 0.702900 ;
    PORT
      LAYER met3 ;
        RECT 733.070 142.840 733.670 143.440 ;
    END
  END result_flat[160]
  PIN result_flat[161]
    DIRECTION OUTPUT ;
    USE SIGNAL ;
    ANTENNADIFFAREA 0.702900 ;
    PORT
      LAYER met3 ;
        RECT 733.070 130.600 733.670 131.200 ;
    END
  END result_flat[161]
  PIN result_flat[162]
    DIRECTION OUTPUT ;
    USE SIGNAL ;
    ANTENNADIFFAREA 0.702900 ;
    PORT
      LAYER met3 ;
        RECT 733.070 167.320 733.670 167.920 ;
    END
  END result_flat[162]
  PIN result_flat[163]
    DIRECTION OUTPUT ;
    USE SIGNAL ;
    ANTENNADIFFAREA 0.702900 ;
    PORT
      LAYER met3 ;
        RECT 733.070 163.240 733.670 163.840 ;
    END
  END result_flat[163]
  PIN result_flat[164]
    DIRECTION OUTPUT ;
    USE SIGNAL ;
    ANTENNADIFFAREA 0.702900 ;
    PORT
      LAYER met3 ;
        RECT 733.070 172.760 733.670 173.360 ;
    END
  END result_flat[164]
  PIN result_flat[165]
    DIRECTION OUTPUT ;
    USE SIGNAL ;
    ANTENNADIFFAREA 0.702900 ;
    PORT
      LAYER met3 ;
        RECT 733.070 176.840 733.670 177.440 ;
    END
  END result_flat[165]
  PIN result_flat[166]
    DIRECTION OUTPUT ;
    USE SIGNAL ;
    ANTENNADIFFAREA 0.702900 ;
    PORT
      LAYER met3 ;
        RECT 733.070 156.440 733.670 157.040 ;
    END
  END result_flat[166]
  PIN result_flat[167]
    DIRECTION OUTPUT ;
    USE SIGNAL ;
    ANTENNADIFFAREA 0.702900 ;
    PORT
      LAYER met3 ;
        RECT 733.070 210.840 733.670 211.440 ;
    END
  END result_flat[167]
  PIN result_flat[168]
    DIRECTION OUTPUT ;
    USE SIGNAL ;
    ANTENNADIFFAREA 0.702900 ;
    PORT
      LAYER met3 ;
        RECT 733.070 187.720 733.670 188.320 ;
    END
  END result_flat[168]
  PIN result_flat[169]
    DIRECTION OUTPUT ;
    USE SIGNAL ;
    ANTENNADIFFAREA 0.702900 ;
    PORT
      LAYER met3 ;
        RECT 733.070 180.920 733.670 181.520 ;
    END
  END result_flat[169]
  PIN result_flat[16]
    DIRECTION OUTPUT ;
    USE SIGNAL ;
    ANTENNADIFFAREA 0.702900 ;
    PORT
      LAYER met2 ;
        RECT 469.290 0.000 469.570 0.280 ;
    END
  END result_flat[16]
  PIN result_flat[170]
    DIRECTION OUTPUT ;
    USE SIGNAL ;
    ANTENNADIFFAREA 0.702900 ;
    PORT
      LAYER met3 ;
        RECT 733.070 193.160 733.670 193.760 ;
    END
  END result_flat[170]
  PIN result_flat[171]
    DIRECTION OUTPUT ;
    USE SIGNAL ;
    ANTENNADIFFAREA 0.702900 ;
    PORT
      LAYER met3 ;
        RECT 733.070 198.600 733.670 199.200 ;
    END
  END result_flat[171]
  PIN result_flat[172]
    DIRECTION OUTPUT ;
    USE SIGNAL ;
    ANTENNADIFFAREA 0.702900 ;
    PORT
      LAYER met3 ;
        RECT 733.070 214.920 733.670 215.520 ;
    END
  END result_flat[172]
  PIN result_flat[173]
    DIRECTION OUTPUT ;
    USE SIGNAL ;
    ANTENNADIFFAREA 0.702900 ;
    PORT
      LAYER met3 ;
        RECT 733.070 217.640 733.670 218.240 ;
    END
  END result_flat[173]
  PIN result_flat[174]
    DIRECTION OUTPUT ;
    USE SIGNAL ;
    ANTENNADIFFAREA 0.702900 ;
    PORT
      LAYER met3 ;
        RECT 733.070 208.120 733.670 208.720 ;
    END
  END result_flat[174]
  PIN result_flat[175]
    DIRECTION OUTPUT ;
    USE SIGNAL ;
    ANTENNADIFFAREA 0.702900 ;
    PORT
      LAYER met3 ;
        RECT 733.070 161.880 733.670 162.480 ;
    END
  END result_flat[175]
  PIN result_flat[176]
    DIRECTION OUTPUT ;
    USE SIGNAL ;
    ANTENNADIFFAREA 0.702900 ;
    PORT
      LAYER met3 ;
        RECT 733.070 236.680 733.670 237.280 ;
    END
  END result_flat[176]
  PIN result_flat[177]
    DIRECTION OUTPUT ;
    USE SIGNAL ;
    ANTENNADIFFAREA 0.702900 ;
    PORT
      LAYER met3 ;
        RECT 733.070 224.440 733.670 225.040 ;
    END
  END result_flat[177]
  PIN result_flat[178]
    DIRECTION OUTPUT ;
    USE SIGNAL ;
    ANTENNADIFFAREA 0.702900 ;
    PORT
      LAYER met3 ;
        RECT 733.070 235.320 733.670 235.920 ;
    END
  END result_flat[178]
  PIN result_flat[179]
    DIRECTION OUTPUT ;
    USE SIGNAL ;
    ANTENNADIFFAREA 0.702900 ;
    PORT
      LAYER met3 ;
        RECT 733.070 369.960 733.670 370.560 ;
    END
  END result_flat[179]
  PIN result_flat[17]
    DIRECTION OUTPUT ;
    USE SIGNAL ;
    ANTENNADIFFAREA 0.702900 ;
    PORT
      LAYER met3 ;
        RECT 733.070 299.240 733.670 299.840 ;
    END
  END result_flat[17]
  PIN result_flat[180]
    DIRECTION OUTPUT ;
    USE SIGNAL ;
    ANTENNADIFFAREA 0.702900 ;
    PORT
      LAYER met3 ;
        RECT 733.070 384.920 733.670 385.520 ;
    END
  END result_flat[180]
  PIN result_flat[181]
    DIRECTION OUTPUT ;
    USE SIGNAL ;
    ANTENNADIFFAREA 0.702900 ;
    PORT
      LAYER met3 ;
        RECT 733.070 221.720 733.670 222.320 ;
    END
  END result_flat[181]
  PIN result_flat[182]
    DIRECTION OUTPUT ;
    USE SIGNAL ;
    ANTENNADIFFAREA 0.702900 ;
    PORT
      LAYER met3 ;
        RECT 733.070 243.480 733.670 244.080 ;
    END
  END result_flat[182]
  PIN result_flat[183]
    DIRECTION OUTPUT ;
    USE SIGNAL ;
    ANTENNADIFFAREA 0.702900 ;
    PORT
      LAYER met3 ;
        RECT 733.070 433.880 733.670 434.480 ;
    END
  END result_flat[183]
  PIN result_flat[184]
    DIRECTION OUTPUT ;
    USE SIGNAL ;
    ANTENNADIFFAREA 0.702900 ;
    PORT
      LAYER met3 ;
        RECT 733.070 421.640 733.670 422.240 ;
    END
  END result_flat[184]
  PIN result_flat[185]
    DIRECTION OUTPUT ;
    USE SIGNAL ;
    ANTENNADIFFAREA 0.702900 ;
    PORT
      LAYER met3 ;
        RECT 733.070 429.800 733.670 430.400 ;
    END
  END result_flat[185]
  PIN result_flat[186]
    DIRECTION OUTPUT ;
    USE SIGNAL ;
    ANTENNADIFFAREA 0.702900 ;
    PORT
      LAYER met3 ;
        RECT 733.070 406.680 733.670 407.280 ;
    END
  END result_flat[186]
  PIN result_flat[187]
    DIRECTION OUTPUT ;
    USE SIGNAL ;
    ANTENNADIFFAREA 0.702900 ;
    PORT
      LAYER met3 ;
        RECT 733.070 436.600 733.670 437.200 ;
    END
  END result_flat[187]
  PIN result_flat[188]
    DIRECTION OUTPUT ;
    USE SIGNAL ;
    ANTENNADIFFAREA 0.702900 ;
    PORT
      LAYER met3 ;
        RECT 733.070 425.720 733.670 426.320 ;
    END
  END result_flat[188]
  PIN result_flat[189]
    DIRECTION OUTPUT ;
    USE SIGNAL ;
    ANTENNADIFFAREA 0.702900 ;
    PORT
      LAYER met3 ;
        RECT 733.070 446.120 733.670 446.720 ;
    END
  END result_flat[189]
  PIN result_flat[18]
    DIRECTION OUTPUT ;
    USE SIGNAL ;
    ANTENNADIFFAREA 0.702900 ;
    PORT
      LAYER met2 ;
        RECT 438.930 0.000 439.210 0.280 ;
    END
  END result_flat[18]
  PIN result_flat[190]
    DIRECTION OUTPUT ;
    USE SIGNAL ;
    ANTENNADIFFAREA 0.702900 ;
    PORT
      LAYER met3 ;
        RECT 733.070 401.240 733.670 401.840 ;
    END
  END result_flat[190]
  PIN result_flat[191]
    DIRECTION OUTPUT ;
    USE SIGNAL ;
    ANTENNADIFFAREA 0.702900 ;
    PORT
      LAYER met3 ;
        RECT 733.070 408.040 733.670 408.640 ;
    END
  END result_flat[191]
  PIN result_flat[192]
    DIRECTION OUTPUT ;
    USE SIGNAL ;
    ANTENNADIFFAREA 0.702900 ;
    PORT
      LAYER met2 ;
        RECT 413.170 744.110 413.450 744.390 ;
    END
  END result_flat[192]
  PIN result_flat[193]
    DIRECTION OUTPUT ;
    USE SIGNAL ;
    ANTENNADIFFAREA 0.702900 ;
    PORT
      LAYER met2 ;
        RECT 405.810 744.110 406.090 744.390 ;
    END
  END result_flat[193]
  PIN result_flat[194]
    DIRECTION OUTPUT ;
    USE SIGNAL ;
    ANTENNADIFFAREA 0.702900 ;
    PORT
      LAYER met2 ;
        RECT 271.490 744.110 271.770 744.390 ;
    END
  END result_flat[194]
  PIN result_flat[195]
    DIRECTION OUTPUT ;
    USE SIGNAL ;
    ANTENNADIFFAREA 0.702900 ;
    PORT
      LAYER met2 ;
        RECT 404.890 744.110 405.170 744.390 ;
    END
  END result_flat[195]
  PIN result_flat[196]
    DIRECTION OUTPUT ;
    USE SIGNAL ;
    ANTENNADIFFAREA 0.702900 ;
    PORT
      LAYER met2 ;
        RECT 386.490 744.110 386.770 744.390 ;
    END
  END result_flat[196]
  PIN result_flat[197]
    DIRECTION OUTPUT ;
    USE SIGNAL ;
    ANTENNADIFFAREA 0.702900 ;
    PORT
      LAYER met2 ;
        RECT 395.690 744.110 395.970 744.390 ;
    END
  END result_flat[197]
  PIN result_flat[198]
    DIRECTION OUTPUT ;
    USE SIGNAL ;
    ANTENNADIFFAREA 0.702900 ;
    PORT
      LAYER met2 ;
        RECT 376.370 744.110 376.650 744.390 ;
    END
  END result_flat[198]
  PIN result_flat[199]
    DIRECTION OUTPUT ;
    USE SIGNAL ;
    ANTENNADIFFAREA 0.702900 ;
    PORT
      LAYER met2 ;
        RECT 406.730 744.110 407.010 744.390 ;
    END
  END result_flat[199]
  PIN result_flat[19]
    DIRECTION OUTPUT ;
    USE SIGNAL ;
    ANTENNADIFFAREA 0.702900 ;
    PORT
      LAYER met2 ;
        RECT 475.730 0.000 476.010 0.280 ;
    END
  END result_flat[19]
  PIN result_flat[1]
    DIRECTION OUTPUT ;
    USE SIGNAL ;
    ANTENNADIFFAREA 0.702900 ;
    PORT
      LAYER met2 ;
        RECT 390.170 744.110 390.450 744.390 ;
    END
  END result_flat[1]
  PIN result_flat[200]
    DIRECTION OUTPUT ;
    USE SIGNAL ;
    ANTENNADIFFAREA 0.702900 ;
    PORT
      LAYER met2 ;
        RECT 265.050 744.110 265.330 744.390 ;
    END
  END result_flat[200]
  PIN result_flat[201]
    DIRECTION OUTPUT ;
    USE SIGNAL ;
    ANTENNADIFFAREA 0.702900 ;
    PORT
      LAYER met2 ;
        RECT 278.850 744.110 279.130 744.390 ;
    END
  END result_flat[201]
  PIN result_flat[202]
    DIRECTION OUTPUT ;
    USE SIGNAL ;
    ANTENNADIFFAREA 0.702900 ;
    PORT
      LAYER met2 ;
        RECT 294.490 744.110 294.770 744.390 ;
    END
  END result_flat[202]
  PIN result_flat[203]
    DIRECTION OUTPUT ;
    USE SIGNAL ;
    ANTENNADIFFAREA 0.702900 ;
    PORT
      LAYER met2 ;
        RECT 273.330 744.110 273.610 744.390 ;
    END
  END result_flat[203]
  PIN result_flat[204]
    DIRECTION OUTPUT ;
    USE SIGNAL ;
    ANTENNADIFFAREA 0.702900 ;
    PORT
      LAYER met2 ;
        RECT 392.930 744.110 393.210 744.390 ;
    END
  END result_flat[204]
  PIN result_flat[205]
    DIRECTION OUTPUT ;
    USE SIGNAL ;
    ANTENNADIFFAREA 0.702900 ;
    PORT
      LAYER met2 ;
        RECT 272.410 744.110 272.690 744.390 ;
    END
  END result_flat[205]
  PIN result_flat[206]
    DIRECTION OUTPUT ;
    USE SIGNAL ;
    ANTENNADIFFAREA 0.702900 ;
    PORT
      LAYER met2 ;
        RECT 284.370 744.110 284.650 744.390 ;
    END
  END result_flat[206]
  PIN result_flat[207]
    DIRECTION OUTPUT ;
    USE SIGNAL ;
    ANTENNADIFFAREA 0.702900 ;
    PORT
      LAYER met2 ;
        RECT 254.930 744.110 255.210 744.390 ;
    END
  END result_flat[207]
  PIN result_flat[208]
    DIRECTION OUTPUT ;
    USE SIGNAL ;
    ANTENNADIFFAREA 0.702900 ;
    PORT
      LAYER met2 ;
        RECT 497.810 0.000 498.090 0.280 ;
    END
  END result_flat[208]
  PIN result_flat[209]
    DIRECTION OUTPUT ;
    USE SIGNAL ;
    ANTENNADIFFAREA 0.702900 ;
    PORT
      LAYER met3 ;
        RECT 733.070 300.600 733.670 301.200 ;
    END
  END result_flat[209]
  PIN result_flat[20]
    DIRECTION OUTPUT ;
    USE SIGNAL ;
    ANTENNADIFFAREA 0.702900 ;
    PORT
      LAYER met2 ;
        RECT 473.890 0.000 474.170 0.280 ;
    END
  END result_flat[20]
  PIN result_flat[210]
    DIRECTION OUTPUT ;
    USE SIGNAL ;
    ANTENNADIFFAREA 0.702900 ;
    PORT
      LAYER met2 ;
        RECT 450.890 0.000 451.170 0.280 ;
    END
  END result_flat[210]
  PIN result_flat[211]
    DIRECTION OUTPUT ;
    USE SIGNAL ;
    ANTENNADIFFAREA 0.702900 ;
    PORT
      LAYER met2 ;
        RECT 496.890 0.000 497.170 0.280 ;
    END
  END result_flat[211]
  PIN result_flat[212]
    DIRECTION OUTPUT ;
    USE SIGNAL ;
    ANTENNADIFFAREA 0.702900 ;
    PORT
      LAYER met2 ;
        RECT 495.970 0.000 496.250 0.280 ;
    END
  END result_flat[212]
  PIN result_flat[213]
    DIRECTION OUTPUT ;
    USE SIGNAL ;
    ANTENNADIFFAREA 0.702900 ;
    PORT
      LAYER met2 ;
        RECT 484.010 0.000 484.290 0.280 ;
    END
  END result_flat[213]
  PIN result_flat[214]
    DIRECTION OUTPUT ;
    USE SIGNAL ;
    ANTENNADIFFAREA 0.702900 ;
    PORT
      LAYER met2 ;
        RECT 501.490 0.000 501.770 0.280 ;
    END
  END result_flat[214]
  PIN result_flat[215]
    DIRECTION OUTPUT ;
    USE SIGNAL ;
    ANTENNADIFFAREA 0.702900 ;
    PORT
      LAYER met2 ;
        RECT 495.050 0.000 495.330 0.280 ;
    END
  END result_flat[215]
  PIN result_flat[216]
    DIRECTION OUTPUT ;
    USE SIGNAL ;
    ANTENNADIFFAREA 0.702900 ;
    PORT
      LAYER met2 ;
        RECT 470.210 0.000 470.490 0.280 ;
    END
  END result_flat[216]
  PIN result_flat[217]
    DIRECTION OUTPUT ;
    USE SIGNAL ;
    ANTENNADIFFAREA 0.702900 ;
    PORT
      LAYER met2 ;
        RECT 490.450 0.000 490.730 0.280 ;
    END
  END result_flat[217]
  PIN result_flat[218]
    DIRECTION OUTPUT ;
    USE SIGNAL ;
    ANTENNADIFFAREA 0.702900 ;
    PORT
      LAYER met3 ;
        RECT 733.070 310.120 733.670 310.720 ;
    END
  END result_flat[218]
  PIN result_flat[219]
    DIRECTION OUTPUT ;
    USE SIGNAL ;
    ANTENNADIFFAREA 0.702900 ;
    PORT
      LAYER met2 ;
        RECT 493.210 0.000 493.490 0.280 ;
    END
  END result_flat[219]
  PIN result_flat[21]
    DIRECTION OUTPUT ;
    USE SIGNAL ;
    ANTENNADIFFAREA 0.702900 ;
    PORT
      LAYER met2 ;
        RECT 481.250 0.000 481.530 0.280 ;
    END
  END result_flat[21]
  PIN result_flat[220]
    DIRECTION OUTPUT ;
    USE SIGNAL ;
    ANTENNADIFFAREA 0.702900 ;
    PORT
      LAYER met2 ;
        RECT 502.410 0.000 502.690 0.280 ;
    END
  END result_flat[220]
  PIN result_flat[221]
    DIRECTION OUTPUT ;
    USE SIGNAL ;
    ANTENNADIFFAREA 0.702900 ;
    PORT
      LAYER met3 ;
        RECT 733.070 318.280 733.670 318.880 ;
    END
  END result_flat[221]
  PIN result_flat[222]
    DIRECTION OUTPUT ;
    USE SIGNAL ;
    ANTENNADIFFAREA 0.702900 ;
    PORT
      LAYER met2 ;
        RECT 477.570 0.000 477.850 0.280 ;
    END
  END result_flat[222]
  PIN result_flat[223]
    DIRECTION OUTPUT ;
    USE SIGNAL ;
    ANTENNADIFFAREA 0.702900 ;
    PORT
      LAYER met3 ;
        RECT 733.070 314.200 733.670 314.800 ;
    END
  END result_flat[223]
  PIN result_flat[224]
    DIRECTION OUTPUT ;
    USE SIGNAL ;
    ANTENNADIFFAREA 0.702900 ;
    PORT
      LAYER met3 ;
        RECT 733.070 145.560 733.670 146.160 ;
    END
  END result_flat[224]
  PIN result_flat[225]
    DIRECTION OUTPUT ;
    USE SIGNAL ;
    ANTENNADIFFAREA 0.702900 ;
    PORT
      LAYER met3 ;
        RECT 733.070 129.240 733.670 129.840 ;
    END
  END result_flat[225]
  PIN result_flat[226]
    DIRECTION OUTPUT ;
    USE SIGNAL ;
    ANTENNADIFFAREA 0.702900 ;
    PORT
      LAYER met3 ;
        RECT 733.070 149.640 733.670 150.240 ;
    END
  END result_flat[226]
  PIN result_flat[227]
    DIRECTION OUTPUT ;
    USE SIGNAL ;
    ANTENNADIFFAREA 0.702900 ;
    PORT
      LAYER met3 ;
        RECT 733.070 164.600 733.670 165.200 ;
    END
  END result_flat[227]
  PIN result_flat[228]
    DIRECTION OUTPUT ;
    USE SIGNAL ;
    ANTENNADIFFAREA 0.702900 ;
    PORT
      LAYER met3 ;
        RECT 733.070 170.040 733.670 170.640 ;
    END
  END result_flat[228]
  PIN result_flat[229]
    DIRECTION OUTPUT ;
    USE SIGNAL ;
    ANTENNADIFFAREA 0.702900 ;
    PORT
      LAYER met3 ;
        RECT 733.070 178.200 733.670 178.800 ;
    END
  END result_flat[229]
  PIN result_flat[22]
    DIRECTION OUTPUT ;
    USE SIGNAL ;
    ANTENNADIFFAREA 0.702900 ;
    PORT
      LAYER met2 ;
        RECT 471.130 0.000 471.410 0.280 ;
    END
  END result_flat[22]
  PIN result_flat[230]
    DIRECTION OUTPUT ;
    USE SIGNAL ;
    ANTENNADIFFAREA 0.702900 ;
    PORT
      LAYER met3 ;
        RECT 733.070 155.080 733.670 155.680 ;
    END
  END result_flat[230]
  PIN result_flat[231]
    DIRECTION OUTPUT ;
    USE SIGNAL ;
    ANTENNADIFFAREA 0.702900 ;
    PORT
      LAYER met3 ;
        RECT 733.070 202.680 733.670 203.280 ;
    END
  END result_flat[231]
  PIN result_flat[232]
    DIRECTION OUTPUT ;
    USE SIGNAL ;
    ANTENNADIFFAREA 0.702900 ;
    PORT
      LAYER met3 ;
        RECT 733.070 189.080 733.670 189.680 ;
    END
  END result_flat[232]
  PIN result_flat[233]
    DIRECTION OUTPUT ;
    USE SIGNAL ;
    ANTENNADIFFAREA 0.702900 ;
    PORT
      LAYER met3 ;
        RECT 733.070 140.120 733.670 140.720 ;
    END
  END result_flat[233]
  PIN result_flat[234]
    DIRECTION OUTPUT ;
    USE SIGNAL ;
    ANTENNADIFFAREA 0.702900 ;
    PORT
      LAYER met3 ;
        RECT 733.070 194.520 733.670 195.120 ;
    END
  END result_flat[234]
  PIN result_flat[235]
    DIRECTION OUTPUT ;
    USE SIGNAL ;
    ANTENNADIFFAREA 0.702900 ;
    PORT
      LAYER met3 ;
        RECT 733.070 199.960 733.670 200.560 ;
    END
  END result_flat[235]
  PIN result_flat[236]
    DIRECTION OUTPUT ;
    USE SIGNAL ;
    ANTENNADIFFAREA 0.702900 ;
    PORT
      LAYER met3 ;
        RECT 733.070 213.560 733.670 214.160 ;
    END
  END result_flat[236]
  PIN result_flat[237]
    DIRECTION OUTPUT ;
    USE SIGNAL ;
    ANTENNADIFFAREA 0.702900 ;
    PORT
      LAYER met3 ;
        RECT 733.070 216.280 733.670 216.880 ;
    END
  END result_flat[237]
  PIN result_flat[238]
    DIRECTION OUTPUT ;
    USE SIGNAL ;
    ANTENNADIFFAREA 0.702900 ;
    PORT
      LAYER met3 ;
        RECT 733.070 204.040 733.670 204.640 ;
    END
  END result_flat[238]
  PIN result_flat[239]
    DIRECTION OUTPUT ;
    USE SIGNAL ;
    ANTENNADIFFAREA 0.702900 ;
    PORT
      LAYER met3 ;
        RECT 733.070 160.520 733.670 161.120 ;
    END
  END result_flat[239]
  PIN result_flat[23]
    DIRECTION OUTPUT ;
    USE SIGNAL ;
    ANTENNADIFFAREA 0.702900 ;
    PORT
      LAYER met2 ;
        RECT 472.970 0.000 473.250 0.280 ;
    END
  END result_flat[23]
  PIN result_flat[240]
    DIRECTION OUTPUT ;
    USE SIGNAL ;
    ANTENNADIFFAREA 0.702900 ;
    PORT
      LAYER met3 ;
        RECT 733.070 244.840 733.670 245.440 ;
    END
  END result_flat[240]
  PIN result_flat[241]
    DIRECTION OUTPUT ;
    USE SIGNAL ;
    ANTENNADIFFAREA 0.702900 ;
    PORT
      LAYER met3 ;
        RECT 733.070 223.080 733.670 223.680 ;
    END
  END result_flat[241]
  PIN result_flat[242]
    DIRECTION OUTPUT ;
    USE SIGNAL ;
    ANTENNADIFFAREA 0.702900 ;
    PORT
      LAYER met3 ;
        RECT 733.070 233.960 733.670 234.560 ;
    END
  END result_flat[242]
  PIN result_flat[243]
    DIRECTION OUTPUT ;
    USE SIGNAL ;
    ANTENNADIFFAREA 0.702900 ;
    PORT
      LAYER met3 ;
        RECT 733.070 371.320 733.670 371.920 ;
    END
  END result_flat[243]
  PIN result_flat[244]
    DIRECTION OUTPUT ;
    USE SIGNAL ;
    ANTENNADIFFAREA 0.702900 ;
    PORT
      LAYER met3 ;
        RECT 733.070 386.280 733.670 386.880 ;
    END
  END result_flat[244]
  PIN result_flat[245]
    DIRECTION OUTPUT ;
    USE SIGNAL ;
    ANTENNADIFFAREA 0.702900 ;
    PORT
      LAYER met3 ;
        RECT 733.070 219.000 733.670 219.600 ;
    END
  END result_flat[245]
  PIN result_flat[246]
    DIRECTION OUTPUT ;
    USE SIGNAL ;
    ANTENNADIFFAREA 0.702900 ;
    PORT
      LAYER met3 ;
        RECT 733.070 227.160 733.670 227.760 ;
    END
  END result_flat[246]
  PIN result_flat[247]
    DIRECTION OUTPUT ;
    USE SIGNAL ;
    ANTENNADIFFAREA 0.702900 ;
    PORT
      LAYER met3 ;
        RECT 733.070 431.160 733.670 431.760 ;
    END
  END result_flat[247]
  PIN result_flat[248]
    DIRECTION OUTPUT ;
    USE SIGNAL ;
    ANTENNADIFFAREA 0.702900 ;
    PORT
      LAYER met3 ;
        RECT 733.070 423.000 733.670 423.600 ;
    END
  END result_flat[248]
  PIN result_flat[249]
    DIRECTION OUTPUT ;
    USE SIGNAL ;
    ANTENNADIFFAREA 0.702900 ;
    PORT
      LAYER met3 ;
        RECT 733.070 432.520 733.670 433.120 ;
    END
  END result_flat[249]
  PIN result_flat[24]
    DIRECTION OUTPUT ;
    USE SIGNAL ;
    ANTENNADIFFAREA 0.702900 ;
    PORT
      LAYER met2 ;
        RECT 453.650 0.000 453.930 0.280 ;
    END
  END result_flat[24]
  PIN result_flat[250]
    DIRECTION OUTPUT ;
    USE SIGNAL ;
    ANTENNADIFFAREA 0.702900 ;
    PORT
      LAYER met3 ;
        RECT 733.070 412.120 733.670 412.720 ;
    END
  END result_flat[250]
  PIN result_flat[251]
    DIRECTION OUTPUT ;
    USE SIGNAL ;
    ANTENNADIFFAREA 0.702900 ;
    PORT
      LAYER met3 ;
        RECT 733.070 435.240 733.670 435.840 ;
    END
  END result_flat[251]
  PIN result_flat[252]
    DIRECTION OUTPUT ;
    USE SIGNAL ;
    ANTENNADIFFAREA 0.702900 ;
    PORT
      LAYER met3 ;
        RECT 733.070 424.360 733.670 424.960 ;
    END
  END result_flat[252]
  PIN result_flat[253]
    DIRECTION OUTPUT ;
    USE SIGNAL ;
    ANTENNADIFFAREA 0.702900 ;
    PORT
      LAYER met3 ;
        RECT 733.070 451.560 733.670 452.160 ;
    END
  END result_flat[253]
  PIN result_flat[254]
    DIRECTION OUTPUT ;
    USE SIGNAL ;
    ANTENNADIFFAREA 0.702900 ;
    PORT
      LAYER met3 ;
        RECT 733.070 402.600 733.670 403.200 ;
    END
  END result_flat[254]
  PIN result_flat[255]
    DIRECTION OUTPUT ;
    USE SIGNAL ;
    ANTENNADIFFAREA 0.702900 ;
    PORT
      LAYER met3 ;
        RECT 733.070 409.400 733.670 410.000 ;
    END
  END result_flat[255]
  PIN result_flat[25]
    DIRECTION OUTPUT ;
    USE SIGNAL ;
    ANTENNADIFFAREA 0.702900 ;
    PORT
      LAYER met2 ;
        RECT 467.450 0.000 467.730 0.280 ;
    END
  END result_flat[25]
  PIN result_flat[26]
    DIRECTION OUTPUT ;
    USE SIGNAL ;
    ANTENNADIFFAREA 0.702900 ;
    PORT
      LAYER met3 ;
        RECT 733.070 316.920 733.670 317.520 ;
    END
  END result_flat[26]
  PIN result_flat[27]
    DIRECTION OUTPUT ;
    USE SIGNAL ;
    ANTENNADIFFAREA 0.702900 ;
    PORT
      LAYER met2 ;
        RECT 466.530 0.000 466.810 0.280 ;
    END
  END result_flat[27]
  PIN result_flat[28]
    DIRECTION OUTPUT ;
    USE SIGNAL ;
    ANTENNADIFFAREA 0.702900 ;
    PORT
      LAYER met2 ;
        RECT 478.490 0.000 478.770 0.280 ;
    END
  END result_flat[28]
  PIN result_flat[29]
    DIRECTION OUTPUT ;
    USE SIGNAL ;
    ANTENNADIFFAREA 0.702900 ;
    PORT
      LAYER met2 ;
        RECT 480.330 0.000 480.610 0.280 ;
    END
  END result_flat[29]
  PIN result_flat[2]
    DIRECTION OUTPUT ;
    USE SIGNAL ;
    ANTENNADIFFAREA 0.702900 ;
    PORT
      LAYER met2 ;
        RECT 258.610 744.110 258.890 744.390 ;
    END
  END result_flat[2]
  PIN result_flat[30]
    DIRECTION OUTPUT ;
    USE SIGNAL ;
    ANTENNADIFFAREA 0.702900 ;
    PORT
      LAYER met2 ;
        RECT 459.170 0.000 459.450 0.280 ;
    END
  END result_flat[30]
  PIN result_flat[31]
    DIRECTION OUTPUT ;
    USE SIGNAL ;
    ANTENNADIFFAREA 0.702900 ;
    PORT
      LAYER met3 ;
        RECT 733.070 304.680 733.670 305.280 ;
    END
  END result_flat[31]
  PIN result_flat[32]
    DIRECTION OUTPUT ;
    USE SIGNAL ;
    ANTENNADIFFAREA 0.702900 ;
    PORT
      LAYER met3 ;
        RECT 733.070 144.200 733.670 144.800 ;
    END
  END result_flat[32]
  PIN result_flat[33]
    DIRECTION OUTPUT ;
    USE SIGNAL ;
    ANTENNADIFFAREA 0.702900 ;
    PORT
      LAYER met3 ;
        RECT 733.070 137.400 733.670 138.000 ;
    END
  END result_flat[33]
  PIN result_flat[34]
    DIRECTION OUTPUT ;
    USE SIGNAL ;
    ANTENNADIFFAREA 0.702900 ;
    PORT
      LAYER met3 ;
        RECT 733.070 157.800 733.670 158.400 ;
    END
  END result_flat[34]
  PIN result_flat[35]
    DIRECTION OUTPUT ;
    USE SIGNAL ;
    ANTENNADIFFAREA 0.702900 ;
    PORT
      LAYER met3 ;
        RECT 733.070 152.360 733.670 152.960 ;
    END
  END result_flat[35]
  PIN result_flat[36]
    DIRECTION OUTPUT ;
    USE SIGNAL ;
    ANTENNADIFFAREA 0.702900 ;
    PORT
      LAYER met3 ;
        RECT 733.070 175.480 733.670 176.080 ;
    END
  END result_flat[36]
  PIN result_flat[37]
    DIRECTION OUTPUT ;
    USE SIGNAL ;
    ANTENNADIFFAREA 0.702900 ;
    PORT
      LAYER met3 ;
        RECT 733.070 148.280 733.670 148.880 ;
    END
  END result_flat[37]
  PIN result_flat[38]
    DIRECTION OUTPUT ;
    USE SIGNAL ;
    ANTENNADIFFAREA 0.702900 ;
    PORT
      LAYER met3 ;
        RECT 733.070 153.720 733.670 154.320 ;
    END
  END result_flat[38]
  PIN result_flat[39]
    DIRECTION OUTPUT ;
    USE SIGNAL ;
    ANTENNADIFFAREA 0.702900 ;
    PORT
      LAYER met3 ;
        RECT 733.070 191.800 733.670 192.400 ;
    END
  END result_flat[39]
  PIN result_flat[3]
    DIRECTION OUTPUT ;
    USE SIGNAL ;
    ANTENNADIFFAREA 0.702900 ;
    PORT
      LAYER met2 ;
        RECT 383.730 744.110 384.010 744.390 ;
    END
  END result_flat[3]
  PIN result_flat[40]
    DIRECTION OUTPUT ;
    USE SIGNAL ;
    ANTENNADIFFAREA 0.702900 ;
    PORT
      LAYER met3 ;
        RECT 733.070 185.000 733.670 185.600 ;
    END
  END result_flat[40]
  PIN result_flat[41]
    DIRECTION OUTPUT ;
    USE SIGNAL ;
    ANTENNADIFFAREA 0.702900 ;
    PORT
      LAYER met3 ;
        RECT 733.070 179.560 733.670 180.160 ;
    END
  END result_flat[41]
  PIN result_flat[42]
    DIRECTION OUTPUT ;
    USE SIGNAL ;
    ANTENNADIFFAREA 0.702900 ;
    PORT
      LAYER met3 ;
        RECT 733.070 186.360 733.670 186.960 ;
    END
  END result_flat[42]
  PIN result_flat[43]
    DIRECTION OUTPUT ;
    USE SIGNAL ;
    ANTENNADIFFAREA 0.702900 ;
    PORT
      LAYER met3 ;
        RECT 733.070 183.640 733.670 184.240 ;
    END
  END result_flat[43]
  PIN result_flat[44]
    DIRECTION OUTPUT ;
    USE SIGNAL ;
    ANTENNADIFFAREA 0.702900 ;
    PORT
      LAYER met3 ;
        RECT 733.070 212.200 733.670 212.800 ;
    END
  END result_flat[44]
  PIN result_flat[45]
    DIRECTION OUTPUT ;
    USE SIGNAL ;
    ANTENNADIFFAREA 0.702900 ;
    PORT
      LAYER met3 ;
        RECT 733.070 205.400 733.670 206.000 ;
    END
  END result_flat[45]
  PIN result_flat[46]
    DIRECTION OUTPUT ;
    USE SIGNAL ;
    ANTENNADIFFAREA 0.702900 ;
    PORT
      LAYER met3 ;
        RECT 733.070 201.320 733.670 201.920 ;
    END
  END result_flat[46]
  PIN result_flat[47]
    DIRECTION OUTPUT ;
    USE SIGNAL ;
    ANTENNADIFFAREA 0.702900 ;
    PORT
      LAYER met3 ;
        RECT 733.070 171.400 733.670 172.000 ;
    END
  END result_flat[47]
  PIN result_flat[48]
    DIRECTION OUTPUT ;
    USE SIGNAL ;
    ANTENNADIFFAREA 0.702900 ;
    PORT
      LAYER met3 ;
        RECT 733.070 240.760 733.670 241.360 ;
    END
  END result_flat[48]
  PIN result_flat[49]
    DIRECTION OUTPUT ;
    USE SIGNAL ;
    ANTENNADIFFAREA 0.702900 ;
    PORT
      LAYER met3 ;
        RECT 733.070 229.880 733.670 230.480 ;
    END
  END result_flat[49]
  PIN result_flat[4]
    DIRECTION OUTPUT ;
    USE SIGNAL ;
    ANTENNADIFFAREA 0.702900 ;
    PORT
      LAYER met2 ;
        RECT 369.010 744.110 369.290 744.390 ;
    END
  END result_flat[4]
  PIN result_flat[50]
    DIRECTION OUTPUT ;
    USE SIGNAL ;
    ANTENNADIFFAREA 0.702900 ;
    PORT
      LAYER met3 ;
        RECT 733.070 238.040 733.670 238.640 ;
    END
  END result_flat[50]
  PIN result_flat[51]
    DIRECTION OUTPUT ;
    USE SIGNAL ;
    ANTENNADIFFAREA 0.702900 ;
    PORT
      LAYER met3 ;
        RECT 733.070 361.800 733.670 362.400 ;
    END
  END result_flat[51]
  PIN result_flat[52]
    DIRECTION OUTPUT ;
    USE SIGNAL ;
    ANTENNADIFFAREA 0.702900 ;
    PORT
      LAYER met3 ;
        RECT 733.070 375.400 733.670 376.000 ;
    END
  END result_flat[52]
  PIN result_flat[53]
    DIRECTION OUTPUT ;
    USE SIGNAL ;
    ANTENNADIFFAREA 0.702900 ;
    PORT
      LAYER met3 ;
        RECT 733.070 242.120 733.670 242.720 ;
    END
  END result_flat[53]
  PIN result_flat[54]
    DIRECTION OUTPUT ;
    USE SIGNAL ;
    ANTENNADIFFAREA 0.702900 ;
    PORT
      LAYER met3 ;
        RECT 733.070 228.520 733.670 229.120 ;
    END
  END result_flat[54]
  PIN result_flat[55]
    DIRECTION OUTPUT ;
    USE SIGNAL ;
    ANTENNADIFFAREA 0.702900 ;
    PORT
      LAYER met3 ;
        RECT 733.070 437.960 733.670 438.560 ;
    END
  END result_flat[55]
  PIN result_flat[56]
    DIRECTION OUTPUT ;
    USE SIGNAL ;
    ANTENNADIFFAREA 0.702900 ;
    PORT
      LAYER met3 ;
        RECT 733.070 420.280 733.670 420.880 ;
    END
  END result_flat[56]
  PIN result_flat[57]
    DIRECTION OUTPUT ;
    USE SIGNAL ;
    ANTENNADIFFAREA 0.702900 ;
    PORT
      LAYER met3 ;
        RECT 733.070 427.080 733.670 427.680 ;
    END
  END result_flat[57]
  PIN result_flat[58]
    DIRECTION OUTPUT ;
    USE SIGNAL ;
    ANTENNADIFFAREA 0.702900 ;
    PORT
      LAYER met3 ;
        RECT 733.070 414.840 733.670 415.440 ;
    END
  END result_flat[58]
  PIN result_flat[59]
    DIRECTION OUTPUT ;
    USE SIGNAL ;
    ANTENNADIFFAREA 0.702900 ;
    PORT
      LAYER met3 ;
        RECT 733.070 439.320 733.670 439.920 ;
    END
  END result_flat[59]
  PIN result_flat[5]
    DIRECTION OUTPUT ;
    USE SIGNAL ;
    ANTENNADIFFAREA 0.702900 ;
    PORT
      LAYER met2 ;
        RECT 379.130 744.110 379.410 744.390 ;
    END
  END result_flat[5]
  PIN result_flat[60]
    DIRECTION OUTPUT ;
    USE SIGNAL ;
    ANTENNADIFFAREA 0.702900 ;
    PORT
      LAYER met3 ;
        RECT 733.070 418.920 733.670 419.520 ;
    END
  END result_flat[60]
  PIN result_flat[61]
    DIRECTION OUTPUT ;
    USE SIGNAL ;
    ANTENNADIFFAREA 0.702900 ;
    PORT
      LAYER met3 ;
        RECT 733.070 443.400 733.670 444.000 ;
    END
  END result_flat[61]
  PIN result_flat[62]
    DIRECTION OUTPUT ;
    USE SIGNAL ;
    ANTENNADIFFAREA 0.702900 ;
    PORT
      LAYER met3 ;
        RECT 733.070 403.960 733.670 404.560 ;
    END
  END result_flat[62]
  PIN result_flat[63]
    DIRECTION OUTPUT ;
    USE SIGNAL ;
    ANTENNADIFFAREA 0.702900 ;
    PORT
      LAYER met3 ;
        RECT 733.070 410.760 733.670 411.360 ;
    END
  END result_flat[63]
  PIN result_flat[64]
    DIRECTION OUTPUT ;
    USE SIGNAL ;
    ANTENNADIFFAREA 0.702900 ;
    PORT
      LAYER met2 ;
        RECT 403.970 744.110 404.250 744.390 ;
    END
  END result_flat[64]
  PIN result_flat[65]
    DIRECTION OUTPUT ;
    USE SIGNAL ;
    ANTENNADIFFAREA 0.702900 ;
    PORT
      LAYER met2 ;
        RECT 396.610 744.110 396.890 744.390 ;
    END
  END result_flat[65]
  PIN result_flat[66]
    DIRECTION OUTPUT ;
    USE SIGNAL ;
    ANTENNADIFFAREA 0.702900 ;
    PORT
      LAYER met2 ;
        RECT 259.530 744.110 259.810 744.390 ;
    END
  END result_flat[66]
  PIN result_flat[67]
    DIRECTION OUTPUT ;
    USE SIGNAL ;
    ANTENNADIFFAREA 0.702900 ;
    PORT
      LAYER met2 ;
        RECT 391.090 744.110 391.370 744.390 ;
    END
  END result_flat[67]
  PIN result_flat[68]
    DIRECTION OUTPUT ;
    USE SIGNAL ;
    ANTENNADIFFAREA 0.702900 ;
    PORT
      LAYER met2 ;
        RECT 373.610 744.110 373.890 744.390 ;
    END
  END result_flat[68]
  PIN result_flat[69]
    DIRECTION OUTPUT ;
    USE SIGNAL ;
    ANTENNADIFFAREA 0.702900 ;
    PORT
      LAYER met2 ;
        RECT 384.650 744.110 384.930 744.390 ;
    END
  END result_flat[69]
  PIN result_flat[6]
    DIRECTION OUTPUT ;
    USE SIGNAL ;
    ANTENNADIFFAREA 0.702900 ;
    PORT
      LAYER met2 ;
        RECT 360.730 744.110 361.010 744.390 ;
    END
  END result_flat[6]
  PIN result_flat[70]
    DIRECTION OUTPUT ;
    USE SIGNAL ;
    ANTENNADIFFAREA 0.702900 ;
    PORT
      LAYER met2 ;
        RECT 367.170 744.110 367.450 744.390 ;
    END
  END result_flat[70]
  PIN result_flat[71]
    DIRECTION OUTPUT ;
    USE SIGNAL ;
    ANTENNADIFFAREA 0.702900 ;
    PORT
      LAYER met2 ;
        RECT 397.530 744.110 397.810 744.390 ;
    END
  END result_flat[71]
  PIN result_flat[72]
    DIRECTION OUTPUT ;
    USE SIGNAL ;
    ANTENNADIFFAREA 0.702900 ;
    PORT
      LAYER met2 ;
        RECT 256.770 744.110 257.050 744.390 ;
    END
  END result_flat[72]
  PIN result_flat[73]
    DIRECTION OUTPUT ;
    USE SIGNAL ;
    ANTENNADIFFAREA 0.702900 ;
    PORT
      LAYER met2 ;
        RECT 276.090 744.110 276.370 744.390 ;
    END
  END result_flat[73]
  PIN result_flat[74]
    DIRECTION OUTPUT ;
    USE SIGNAL ;
    ANTENNADIFFAREA 0.702900 ;
    PORT
      LAYER met2 ;
        RECT 291.730 744.110 292.010 744.390 ;
    END
  END result_flat[74]
  PIN result_flat[75]
    DIRECTION OUTPUT ;
    USE SIGNAL ;
    ANTENNADIFFAREA 0.702900 ;
    PORT
      LAYER met2 ;
        RECT 267.810 744.110 268.090 744.390 ;
    END
  END result_flat[75]
  PIN result_flat[76]
    DIRECTION OUTPUT ;
    USE SIGNAL ;
    ANTENNADIFFAREA 0.702900 ;
    PORT
      LAYER met2 ;
        RECT 382.810 744.110 383.090 744.390 ;
    END
  END result_flat[76]
  PIN result_flat[77]
    DIRECTION OUTPUT ;
    USE SIGNAL ;
    ANTENNADIFFAREA 0.702900 ;
    PORT
      LAYER met2 ;
        RECT 262.290 744.110 262.570 744.390 ;
    END
  END result_flat[77]
  PIN result_flat[78]
    DIRECTION OUTPUT ;
    USE SIGNAL ;
    ANTENNADIFFAREA 0.702900 ;
    PORT
      LAYER met2 ;
        RECT 280.690 744.110 280.970 744.390 ;
    END
  END result_flat[78]
  PIN result_flat[79]
    DIRECTION OUTPUT ;
    USE SIGNAL ;
    ANTENNADIFFAREA 0.702900 ;
    PORT
      LAYER met2 ;
        RECT 254.010 744.110 254.290 744.390 ;
    END
  END result_flat[79]
  PIN result_flat[7]
    DIRECTION OUTPUT ;
    USE SIGNAL ;
    ANTENNADIFFAREA 0.702900 ;
    PORT
      LAYER met2 ;
        RECT 385.570 744.110 385.850 744.390 ;
    END
  END result_flat[7]
  PIN result_flat[80]
    DIRECTION OUTPUT ;
    USE SIGNAL ;
    ANTENNADIFFAREA 0.702900 ;
    PORT
      LAYER met2 ;
        RECT 474.810 0.000 475.090 0.280 ;
    END
  END result_flat[80]
  PIN result_flat[81]
    DIRECTION OUTPUT ;
    USE SIGNAL ;
    ANTENNADIFFAREA 0.702900 ;
    PORT
      LAYER met3 ;
        RECT 733.070 303.320 733.670 303.920 ;
    END
  END result_flat[81]
  PIN result_flat[82]
    DIRECTION OUTPUT ;
    USE SIGNAL ;
    ANTENNADIFFAREA 0.702900 ;
    PORT
      LAYER met2 ;
        RECT 441.690 0.000 441.970 0.280 ;
    END
  END result_flat[82]
  PIN result_flat[83]
    DIRECTION OUTPUT ;
    USE SIGNAL ;
    ANTENNADIFFAREA 0.702900 ;
    PORT
      LAYER met2 ;
        RECT 483.090 0.000 483.370 0.280 ;
    END
  END result_flat[83]
  PIN result_flat[84]
    DIRECTION OUTPUT ;
    USE SIGNAL ;
    ANTENNADIFFAREA 0.702900 ;
    PORT
      LAYER met2 ;
        RECT 485.850 0.000 486.130 0.280 ;
    END
  END result_flat[84]
  PIN result_flat[85]
    DIRECTION OUTPUT ;
    USE SIGNAL ;
    ANTENNADIFFAREA 0.702900 ;
    PORT
      LAYER met2 ;
        RECT 486.770 0.000 487.050 0.280 ;
    END
  END result_flat[85]
  PIN result_flat[86]
    DIRECTION OUTPUT ;
    USE SIGNAL ;
    ANTENNADIFFAREA 0.702900 ;
    PORT
      LAYER met2 ;
        RECT 494.130 0.000 494.410 0.280 ;
    END
  END result_flat[86]
  PIN result_flat[87]
    DIRECTION OUTPUT ;
    USE SIGNAL ;
    ANTENNADIFFAREA 0.702900 ;
    PORT
      LAYER met2 ;
        RECT 479.410 0.000 479.690 0.280 ;
    END
  END result_flat[87]
  PIN result_flat[88]
    DIRECTION OUTPUT ;
    USE SIGNAL ;
    ANTENNADIFFAREA 0.702900 ;
    PORT
      LAYER met2 ;
        RECT 460.090 0.000 460.370 0.280 ;
    END
  END result_flat[88]
  PIN result_flat[89]
    DIRECTION OUTPUT ;
    USE SIGNAL ;
    ANTENNADIFFAREA 0.702900 ;
    PORT
      LAYER met2 ;
        RECT 472.050 0.000 472.330 0.280 ;
    END
  END result_flat[89]
  PIN result_flat[8]
    DIRECTION OUTPUT ;
    USE SIGNAL ;
    ANTENNADIFFAREA 0.702900 ;
    PORT
      LAYER met2 ;
        RECT 257.690 744.110 257.970 744.390 ;
    END
  END result_flat[8]
  PIN result_flat[90]
    DIRECTION OUTPUT ;
    USE SIGNAL ;
    ANTENNADIFFAREA 0.702900 ;
    PORT
      LAYER met3 ;
        RECT 733.070 312.840 733.670 313.440 ;
    END
  END result_flat[90]
  PIN result_flat[91]
    DIRECTION OUTPUT ;
    USE SIGNAL ;
    ANTENNADIFFAREA 0.702900 ;
    PORT
      LAYER met2 ;
        RECT 476.650 0.000 476.930 0.280 ;
    END
  END result_flat[91]
  PIN result_flat[92]
    DIRECTION OUTPUT ;
    USE SIGNAL ;
    ANTENNADIFFAREA 0.702900 ;
    PORT
      LAYER met2 ;
        RECT 492.290 0.000 492.570 0.280 ;
    END
  END result_flat[92]
  PIN result_flat[93]
    DIRECTION OUTPUT ;
    USE SIGNAL ;
    ANTENNADIFFAREA 0.702900 ;
    PORT
      LAYER met3 ;
        RECT 733.070 315.560 733.670 316.160 ;
    END
  END result_flat[93]
  PIN result_flat[94]
    DIRECTION OUTPUT ;
    USE SIGNAL ;
    ANTENNADIFFAREA 0.702900 ;
    PORT
      LAYER met2 ;
        RECT 465.610 0.000 465.890 0.280 ;
    END
  END result_flat[94]
  PIN result_flat[95]
    DIRECTION OUTPUT ;
    USE SIGNAL ;
    ANTENNADIFFAREA 0.702900 ;
    PORT
      LAYER met3 ;
        RECT 733.070 306.040 733.670 306.640 ;
    END
  END result_flat[95]
  PIN result_flat[96]
    DIRECTION OUTPUT ;
    USE SIGNAL ;
    ANTENNADIFFAREA 0.702900 ;
    PORT
      LAYER met3 ;
        RECT 733.070 146.920 733.670 147.520 ;
    END
  END result_flat[96]
  PIN result_flat[97]
    DIRECTION OUTPUT ;
    USE SIGNAL ;
    ANTENNADIFFAREA 0.702900 ;
    PORT
      LAYER met3 ;
        RECT 733.070 136.040 733.670 136.640 ;
    END
  END result_flat[97]
  PIN result_flat[98]
    DIRECTION OUTPUT ;
    USE SIGNAL ;
    ANTENNADIFFAREA 0.702900 ;
    PORT
      LAYER met3 ;
        RECT 733.070 165.960 733.670 166.560 ;
    END
  END result_flat[98]
  PIN result_flat[99]
    DIRECTION OUTPUT ;
    USE SIGNAL ;
    ANTENNADIFFAREA 0.702900 ;
    PORT
      LAYER met3 ;
        RECT 733.070 159.160 733.670 159.760 ;
    END
  END result_flat[99]
  PIN result_flat[9]
    DIRECTION OUTPUT ;
    USE SIGNAL ;
    ANTENNADIFFAREA 0.702900 ;
    PORT
      LAYER met2 ;
        RECT 274.250 744.110 274.530 744.390 ;
    END
  END result_flat[9]
  PIN result_valid
    DIRECTION OUTPUT ;
    USE SIGNAL ;
    ANTENNADIFFAREA 0.702900 ;
    PORT
      LAYER met2 ;
        RECT 411.330 744.110 411.610 744.390 ;
    END
  END result_valid
  PIN rst
    DIRECTION INPUT ;
    USE SIGNAL ;
    ANTENNAGATEAREA 0.213000 ;
    PORT
      LAYER met3 ;
        RECT 733.070 15.000 733.670 15.600 ;
    END
  END rst
  PIN start
    DIRECTION INPUT ;
    USE SIGNAL ;
    ANTENNAGATEAREA 0.213000 ;
    PORT
      LAYER met2 ;
        RECT 494.130 744.110 494.410 744.390 ;
    END
  END start
  OBS
      LAYER nwell ;
        RECT 5.330 10.795 727.910 731.870 ;
      LAYER li1 ;
        RECT 5.520 10.795 727.720 731.765 ;
      LAYER met1 ;
        RECT 0.530 0.040 733.630 744.220 ;
      LAYER met2 ;
        RECT 0.550 743.830 245.450 744.320 ;
        RECT 246.290 743.830 250.050 744.320 ;
        RECT 250.890 743.830 252.810 744.320 ;
        RECT 253.650 743.830 253.730 744.320 ;
        RECT 254.570 743.830 254.650 744.320 ;
        RECT 255.490 743.830 255.570 744.320 ;
        RECT 256.410 743.830 256.490 744.320 ;
        RECT 257.330 743.830 257.410 744.320 ;
        RECT 258.250 743.830 258.330 744.320 ;
        RECT 259.170 743.830 259.250 744.320 ;
        RECT 260.090 743.830 260.170 744.320 ;
        RECT 261.010 743.830 261.090 744.320 ;
        RECT 261.930 743.830 262.010 744.320 ;
        RECT 262.850 743.830 262.930 744.320 ;
        RECT 263.770 743.830 263.850 744.320 ;
        RECT 264.690 743.830 264.770 744.320 ;
        RECT 265.610 743.830 265.690 744.320 ;
        RECT 266.530 743.830 266.610 744.320 ;
        RECT 267.450 743.830 267.530 744.320 ;
        RECT 268.370 743.830 268.450 744.320 ;
        RECT 269.290 743.830 269.370 744.320 ;
        RECT 270.210 743.830 270.290 744.320 ;
        RECT 271.130 743.830 271.210 744.320 ;
        RECT 272.050 743.830 272.130 744.320 ;
        RECT 272.970 743.830 273.050 744.320 ;
        RECT 273.890 743.830 273.970 744.320 ;
        RECT 274.810 743.830 275.810 744.320 ;
        RECT 276.650 743.830 276.730 744.320 ;
        RECT 277.570 743.830 277.650 744.320 ;
        RECT 278.490 743.830 278.570 744.320 ;
        RECT 279.410 743.830 279.490 744.320 ;
        RECT 280.330 743.830 280.410 744.320 ;
        RECT 281.250 743.830 281.330 744.320 ;
        RECT 282.170 743.830 282.250 744.320 ;
        RECT 283.090 743.830 283.170 744.320 ;
        RECT 284.010 743.830 284.090 744.320 ;
        RECT 284.930 743.830 286.850 744.320 ;
        RECT 287.690 743.830 287.770 744.320 ;
        RECT 288.610 743.830 290.530 744.320 ;
        RECT 291.370 743.830 291.450 744.320 ;
        RECT 292.290 743.830 292.370 744.320 ;
        RECT 293.210 743.830 293.290 744.320 ;
        RECT 294.130 743.830 294.210 744.320 ;
        RECT 295.050 743.830 299.730 744.320 ;
        RECT 300.570 743.830 300.650 744.320 ;
        RECT 301.490 743.830 308.010 744.320 ;
        RECT 308.850 743.830 309.850 744.320 ;
        RECT 310.690 743.830 319.050 744.320 ;
        RECT 319.890 743.830 326.410 744.320 ;
        RECT 327.250 743.830 330.090 744.320 ;
        RECT 330.930 743.830 352.170 744.320 ;
        RECT 353.010 743.830 360.450 744.320 ;
        RECT 361.290 743.830 366.890 744.320 ;
        RECT 367.730 743.830 368.730 744.320 ;
        RECT 369.570 743.830 372.410 744.320 ;
        RECT 373.250 743.830 373.330 744.320 ;
        RECT 374.170 743.830 374.250 744.320 ;
        RECT 375.090 743.830 376.090 744.320 ;
        RECT 376.930 743.830 377.010 744.320 ;
        RECT 377.850 743.830 378.850 744.320 ;
        RECT 379.690 743.830 379.770 744.320 ;
        RECT 380.610 743.830 381.610 744.320 ;
        RECT 382.450 743.830 382.530 744.320 ;
        RECT 383.370 743.830 383.450 744.320 ;
        RECT 384.290 743.830 384.370 744.320 ;
        RECT 385.210 743.830 385.290 744.320 ;
        RECT 386.130 743.830 386.210 744.320 ;
        RECT 387.050 743.830 387.130 744.320 ;
        RECT 387.970 743.830 388.050 744.320 ;
        RECT 388.890 743.830 388.970 744.320 ;
        RECT 389.810 743.830 389.890 744.320 ;
        RECT 390.730 743.830 390.810 744.320 ;
        RECT 391.650 743.830 391.730 744.320 ;
        RECT 392.570 743.830 392.650 744.320 ;
        RECT 393.490 743.830 393.570 744.320 ;
        RECT 394.410 743.830 394.490 744.320 ;
        RECT 395.330 743.830 395.410 744.320 ;
        RECT 396.250 743.830 396.330 744.320 ;
        RECT 397.170 743.830 397.250 744.320 ;
        RECT 398.090 743.830 398.170 744.320 ;
        RECT 399.010 743.830 399.090 744.320 ;
        RECT 399.930 743.830 400.010 744.320 ;
        RECT 400.850 743.830 400.930 744.320 ;
        RECT 401.770 743.830 401.850 744.320 ;
        RECT 402.690 743.830 402.770 744.320 ;
        RECT 403.610 743.830 403.690 744.320 ;
        RECT 404.530 743.830 404.610 744.320 ;
        RECT 405.450 743.830 405.530 744.320 ;
        RECT 406.370 743.830 406.450 744.320 ;
        RECT 407.290 743.830 407.370 744.320 ;
        RECT 408.210 743.830 408.290 744.320 ;
        RECT 409.130 743.830 409.210 744.320 ;
        RECT 410.050 743.830 411.050 744.320 ;
        RECT 411.890 743.830 412.890 744.320 ;
        RECT 413.730 743.830 417.490 744.320 ;
        RECT 418.330 743.830 420.250 744.320 ;
        RECT 421.090 743.830 433.130 744.320 ;
        RECT 433.970 743.830 446.930 744.320 ;
        RECT 447.770 743.830 463.490 744.320 ;
        RECT 464.330 743.830 470.850 744.320 ;
        RECT 471.690 743.830 493.850 744.320 ;
        RECT 494.690 743.830 502.130 744.320 ;
        RECT 502.970 743.830 504.890 744.320 ;
        RECT 505.730 743.830 733.600 744.320 ;
        RECT 0.550 0.560 733.600 743.830 ;
        RECT 0.550 0.010 124.010 0.560 ;
        RECT 124.850 0.010 177.370 0.560 ;
        RECT 178.210 0.010 183.810 0.560 ;
        RECT 184.650 0.010 187.490 0.560 ;
        RECT 188.330 0.010 189.330 0.560 ;
        RECT 190.170 0.010 190.250 0.560 ;
        RECT 191.090 0.010 193.010 0.560 ;
        RECT 193.850 0.010 197.610 0.560 ;
        RECT 198.450 0.010 202.210 0.560 ;
        RECT 203.050 0.010 204.970 0.560 ;
        RECT 205.810 0.010 209.570 0.560 ;
        RECT 210.410 0.010 263.850 0.560 ;
        RECT 264.690 0.010 438.650 0.560 ;
        RECT 439.490 0.010 441.410 0.560 ;
        RECT 442.250 0.010 446.930 0.560 ;
        RECT 447.770 0.010 450.610 0.560 ;
        RECT 451.450 0.010 453.370 0.560 ;
        RECT 454.210 0.010 458.890 0.560 ;
        RECT 459.730 0.010 459.810 0.560 ;
        RECT 460.650 0.010 464.410 0.560 ;
        RECT 465.250 0.010 465.330 0.560 ;
        RECT 466.170 0.010 466.250 0.560 ;
        RECT 467.090 0.010 467.170 0.560 ;
        RECT 468.010 0.010 468.090 0.560 ;
        RECT 468.930 0.010 469.010 0.560 ;
        RECT 469.850 0.010 469.930 0.560 ;
        RECT 470.770 0.010 470.850 0.560 ;
        RECT 471.690 0.010 471.770 0.560 ;
        RECT 472.610 0.010 472.690 0.560 ;
        RECT 473.530 0.010 473.610 0.560 ;
        RECT 474.450 0.010 474.530 0.560 ;
        RECT 475.370 0.010 475.450 0.560 ;
        RECT 476.290 0.010 476.370 0.560 ;
        RECT 477.210 0.010 477.290 0.560 ;
        RECT 478.130 0.010 478.210 0.560 ;
        RECT 479.050 0.010 479.130 0.560 ;
        RECT 479.970 0.010 480.050 0.560 ;
        RECT 480.890 0.010 480.970 0.560 ;
        RECT 481.810 0.010 481.890 0.560 ;
        RECT 482.730 0.010 482.810 0.560 ;
        RECT 483.650 0.010 483.730 0.560 ;
        RECT 484.570 0.010 484.650 0.560 ;
        RECT 485.490 0.010 485.570 0.560 ;
        RECT 486.410 0.010 486.490 0.560 ;
        RECT 487.330 0.010 487.410 0.560 ;
        RECT 488.250 0.010 488.330 0.560 ;
        RECT 489.170 0.010 489.250 0.560 ;
        RECT 490.090 0.010 490.170 0.560 ;
        RECT 491.010 0.010 491.090 0.560 ;
        RECT 491.930 0.010 492.010 0.560 ;
        RECT 492.850 0.010 492.930 0.560 ;
        RECT 493.770 0.010 493.850 0.560 ;
        RECT 494.690 0.010 494.770 0.560 ;
        RECT 495.610 0.010 495.690 0.560 ;
        RECT 496.530 0.010 496.610 0.560 ;
        RECT 497.450 0.010 497.530 0.560 ;
        RECT 498.370 0.010 498.450 0.560 ;
        RECT 499.290 0.010 499.370 0.560 ;
        RECT 500.210 0.010 500.290 0.560 ;
        RECT 501.130 0.010 501.210 0.560 ;
        RECT 502.050 0.010 502.130 0.560 ;
        RECT 502.970 0.010 733.600 0.560 ;
      LAYER met3 ;
        RECT 0.600 727.280 733.070 734.225 ;
        RECT 1.000 725.880 733.070 727.280 ;
        RECT 0.600 550.480 733.070 725.880 ;
        RECT 1.000 549.080 733.070 550.480 ;
        RECT 0.600 545.040 733.070 549.080 ;
        RECT 1.000 543.640 733.070 545.040 ;
        RECT 0.600 456.640 733.070 543.640 ;
        RECT 0.600 455.240 732.670 456.640 ;
        RECT 0.600 452.560 733.070 455.240 ;
        RECT 0.600 451.160 732.670 452.560 ;
        RECT 0.600 447.120 733.070 451.160 ;
        RECT 0.600 438.960 732.670 447.120 ;
        RECT 1.000 436.200 732.670 438.960 ;
        RECT 0.600 429.440 732.670 436.200 ;
        RECT 1.000 425.320 732.670 429.440 ;
        RECT 0.600 424.000 732.670 425.320 ;
        RECT 1.000 422.600 732.670 424.000 ;
        RECT 0.600 419.920 732.670 422.600 ;
        RECT 1.000 415.800 732.670 419.920 ;
        RECT 0.600 414.480 732.670 415.800 ;
        RECT 1.000 400.840 732.670 414.480 ;
        RECT 0.600 399.480 732.670 400.840 ;
        RECT 0.600 396.800 733.070 399.480 ;
        RECT 1.000 387.280 733.070 396.800 ;
        RECT 1.000 385.880 732.670 387.280 ;
        RECT 0.600 384.560 732.670 385.880 ;
        RECT 1.000 384.520 732.670 384.560 ;
        RECT 1.000 379.120 733.070 384.520 ;
        RECT 1.000 377.720 732.670 379.120 ;
        RECT 1.000 376.400 733.070 377.720 ;
        RECT 1.000 375.000 732.670 376.400 ;
        RECT 1.000 372.320 733.070 375.000 ;
        RECT 1.000 372.280 732.670 372.320 ;
        RECT 0.600 370.960 732.670 372.280 ;
        RECT 1.000 369.560 732.670 370.960 ;
        RECT 1.000 366.840 733.070 369.560 ;
        RECT 0.600 365.520 733.070 366.840 ;
        RECT 1.000 364.160 733.070 365.520 ;
        RECT 1.000 364.120 732.670 364.160 ;
        RECT 0.600 362.800 732.670 364.120 ;
        RECT 1.000 361.400 732.670 362.800 ;
        RECT 1.000 358.680 733.070 361.400 ;
        RECT 0.600 357.360 733.070 358.680 ;
        RECT 1.000 354.600 733.070 357.360 ;
        RECT 0.600 353.280 733.070 354.600 ;
        RECT 1.000 346.440 733.070 353.280 ;
        RECT 0.600 345.120 733.070 346.440 ;
        RECT 1.000 334.200 733.070 345.120 ;
        RECT 0.600 332.880 733.070 334.200 ;
        RECT 1.000 331.480 733.070 332.880 ;
        RECT 0.600 328.800 733.070 331.480 ;
        RECT 1.000 324.680 733.070 328.800 ;
        RECT 0.600 320.640 733.070 324.680 ;
        RECT 0.600 317.920 732.670 320.640 ;
        RECT 1.000 316.520 732.670 317.920 ;
        RECT 0.600 308.400 732.670 316.520 ;
        RECT 1.000 308.360 732.670 308.400 ;
        RECT 1.000 307.040 733.070 308.360 ;
        RECT 1.000 307.000 732.670 307.040 ;
        RECT 0.600 304.320 732.670 307.000 ;
        RECT 1.000 302.920 732.670 304.320 ;
        RECT 0.600 298.840 732.670 302.920 ;
        RECT 0.600 294.800 733.070 298.840 ;
        RECT 1.000 292.040 733.070 294.800 ;
        RECT 0.600 289.360 733.070 292.040 ;
        RECT 1.000 287.960 733.070 289.360 ;
        RECT 0.600 274.400 733.070 287.960 ;
        RECT 1.000 273.000 733.070 274.400 ;
        RECT 0.600 271.680 733.070 273.000 ;
        RECT 1.000 270.280 733.070 271.680 ;
        RECT 0.600 264.880 733.070 270.280 ;
        RECT 1.000 262.120 733.070 264.880 ;
        RECT 0.600 260.800 733.070 262.120 ;
        RECT 1.000 259.400 733.070 260.800 ;
        RECT 0.600 254.000 733.070 259.400 ;
        RECT 1.000 252.600 733.070 254.000 ;
        RECT 0.600 248.560 733.070 252.600 ;
        RECT 1.000 247.200 733.070 248.560 ;
        RECT 1.000 247.160 732.670 247.200 ;
        RECT 0.600 237.680 732.670 247.160 ;
        RECT 1.000 236.280 732.670 237.680 ;
        RECT 0.600 198.240 732.670 236.280 ;
        RECT 1.000 196.840 732.670 198.240 ;
        RECT 0.600 135.640 732.670 196.840 ;
        RECT 0.600 131.600 733.070 135.640 ;
        RECT 0.600 128.840 732.670 131.600 ;
        RECT 0.600 16.000 733.070 128.840 ;
        RECT 0.600 14.600 732.670 16.000 ;
        RECT 0.600 0.175 733.070 14.600 ;
      LAYER met4 ;
        RECT 10.415 732.320 728.770 734.225 ;
        RECT 10.415 10.240 20.640 732.320 ;
        RECT 23.040 10.240 23.940 732.320 ;
        RECT 26.340 10.240 174.240 732.320 ;
        RECT 176.640 10.240 177.540 732.320 ;
        RECT 179.940 10.240 327.840 732.320 ;
        RECT 330.240 10.240 331.140 732.320 ;
        RECT 333.540 10.240 481.440 732.320 ;
        RECT 483.840 10.240 484.740 732.320 ;
        RECT 487.140 10.240 635.040 732.320 ;
        RECT 637.440 10.240 638.340 732.320 ;
        RECT 640.740 10.240 728.770 732.320 ;
        RECT 10.415 4.255 728.770 10.240 ;
      LAYER met5 ;
        RECT 26.340 645.950 728.980 730.100 ;
        RECT 26.340 492.770 728.980 637.850 ;
        RECT 26.340 339.590 728.980 484.670 ;
        RECT 26.340 186.410 728.980 331.490 ;
        RECT 26.340 34.900 728.980 178.310 ;
  END
END mini_tpu_top
END LIBRARY

